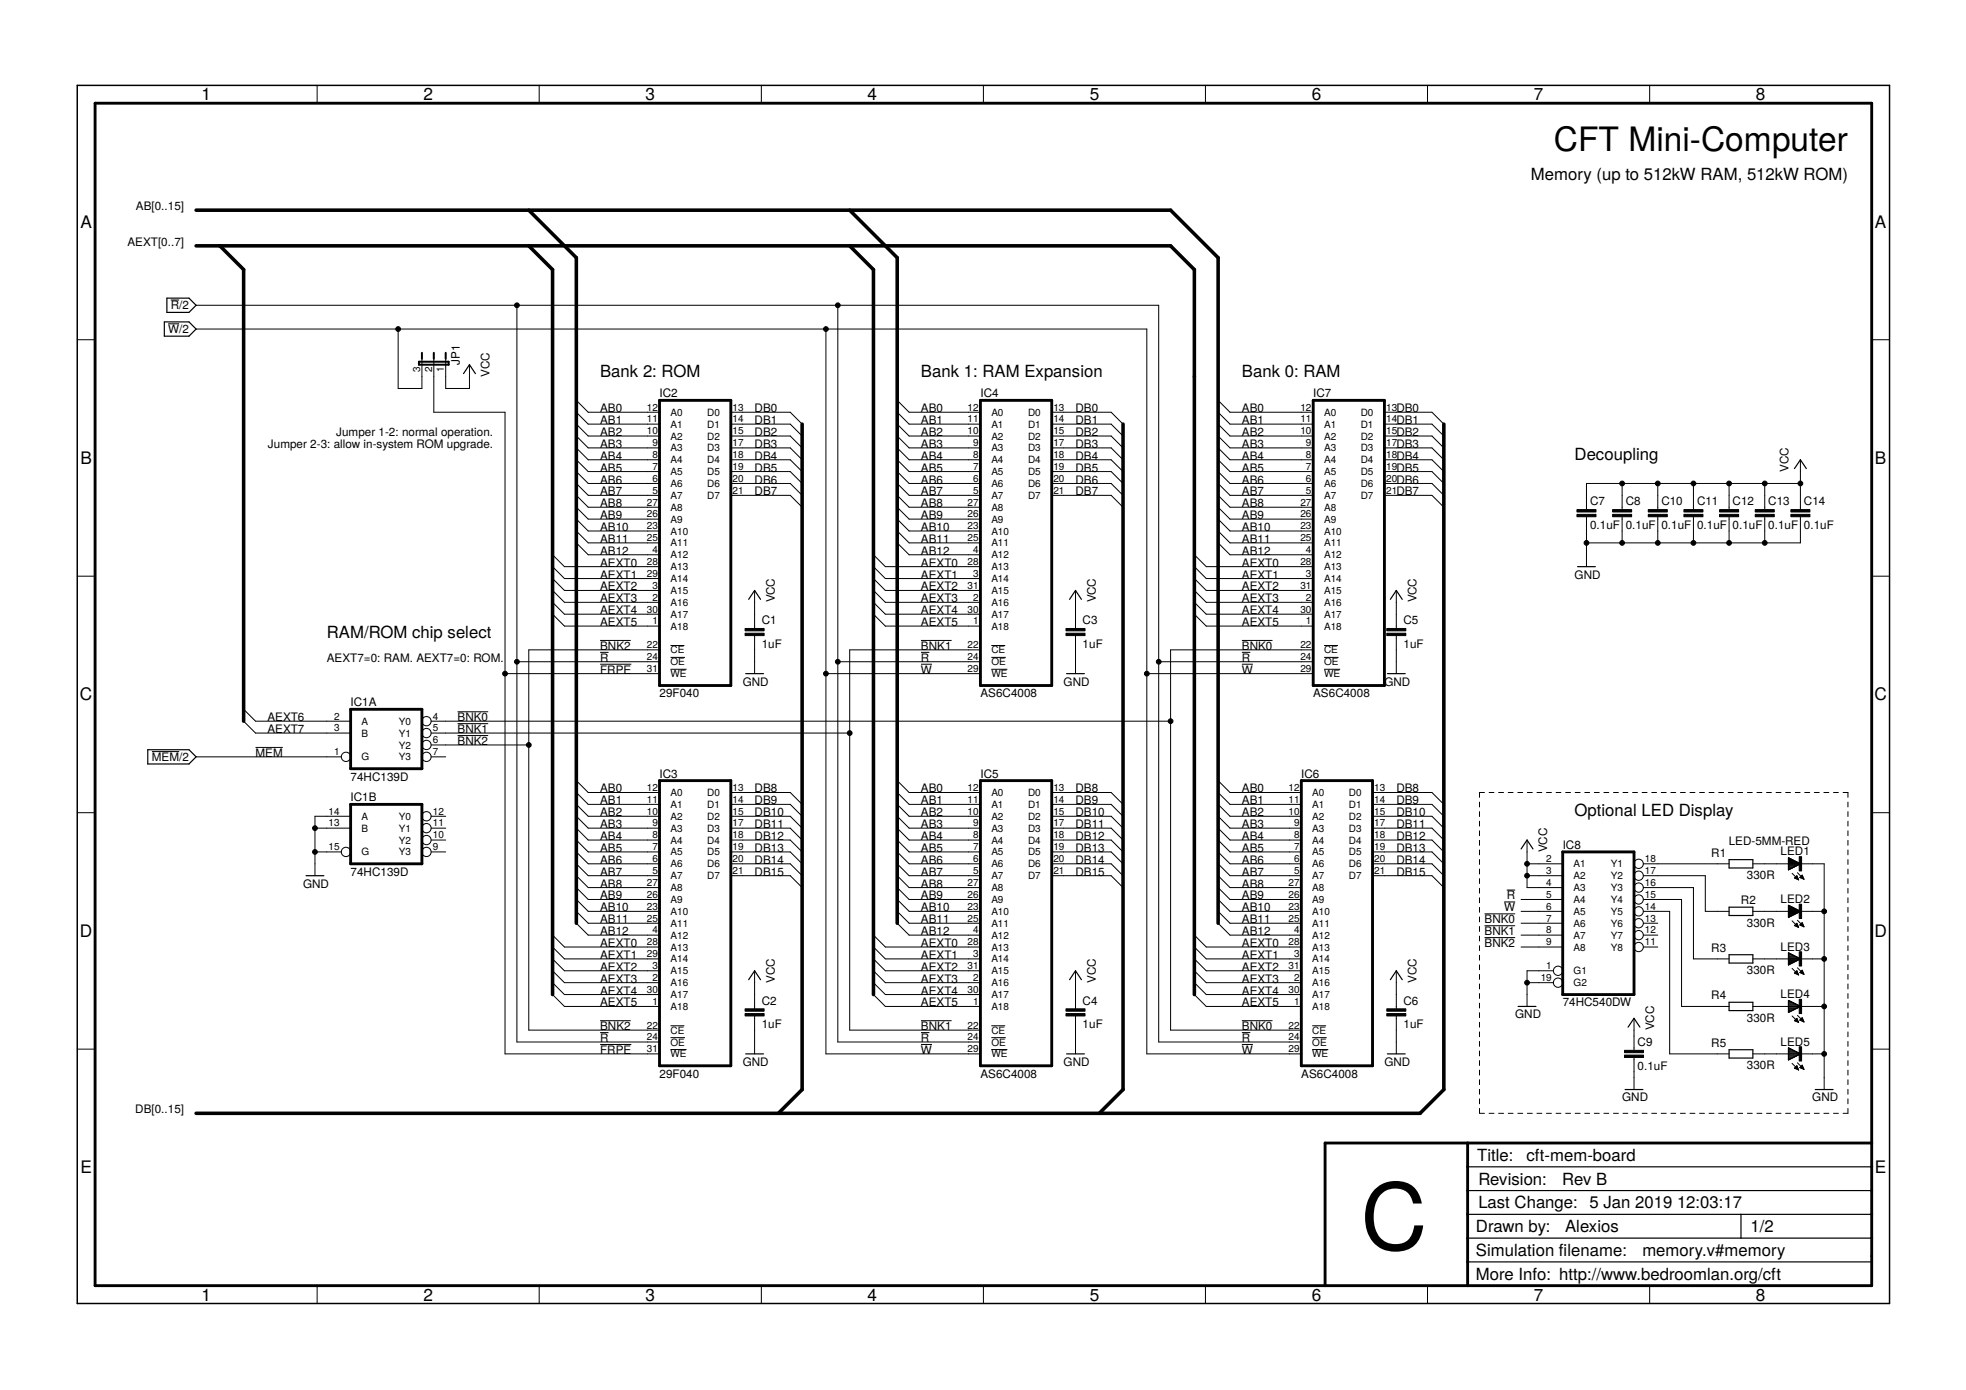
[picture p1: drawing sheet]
<svg xmlns="http://www.w3.org/2000/svg" width="420mm" height="297mm" viewBox="0 0 420 297" stroke-linecap="round" stroke-linejoin="round" font-family="sans-serif">
<defs><g id="words">
<text font-size="19.7" x="290.8" y="267.1">C</text>
<text font-size="7.2" x="332.1" y="32.2">CFT Mini-Computer</text>
<g font-size="3.7">
<text x="43" y="21.4">1</text>
<text x="90.5" y="21.4">2</text>
<text x="138" y="21.4">3</text>
<text x="185.4" y="21.4">4</text>
<text x="232.9" y="21.4">5</text>
<text x="280.3" y="21.4">6</text>
<text x="327.8" y="21.4">7</text>
<text x="375.3" y="21.4">8</text>
<text x="17.2" y="48.6">A</text>
<text x="400.7" y="48.6">A</text>
<text x="17.2" y="99.2">B</text>
<text x="400.7" y="99.2">B</text>
<text x="17.1" y="149.7">C</text>
<text x="400.6" y="149.7">C</text>
<text x="17.1" y="200.2">D</text>
<text x="400.6" y="200.2">D</text>
<text x="17.2" y="250.8">E</text>
<text x="400.7" y="250.8">E</text>
<text x="43" y="277.9">1</text>
<text x="90.5" y="277.9">2</text>
<text x="138" y="277.9">3</text>
<text x="185.4" y="277.9">4</text>
<text x="232.9" y="277.9">5</text>
<text x="280.3" y="277.9">6</text>
<text x="327.8" y="277.9">7</text>
<text x="375.3" y="277.9">8</text>
</g>
<g font-size="3.6">
<text x="327.2" y="38.6">Memory (up to 512kW RAM, 512kW ROM)</text>
<text x="128.3" y="80.5">Bank 2: ROM</text>
<text x="196.8" y="80.5">Bank 1: RAM Expansion</text>
<text x="265.4" y="80.5">Bank 0: RAM</text>
<text x="336.5" y="98.2">Decoupling</text>
<text x="69.8" y="136.3">RAM/ROM chip select</text>
<text x="336.5" y="174.4">Optional LED Display</text>
<text x="315.7" y="248.1">Title:</text>
<text x="326.2" y="248.2">cft-mem-board</text>
<text x="315.9" y="253.2">Revision:</text>
<text x="333.8" y="253.3">Rev B</text>
<text x="315.4" y="263.3">Drawn by:</text>
<text x="315.9" y="258.2">Last Change: 5 Jan 2019</text>
<text x="334.5" y="263.3">Alexios</text>
<text x="358.4" y="258.1">12:03:17</text>
<text x="374.1" y="263.2">1/2</text>
<text x="315.4" y="268.4">Simulation flename:</text>
<text x="333.2" y="268.4">i</text>
<text x="351" y="268.4">memory.v#memory</text>
<text x="315.4" y="273.5">More Info: http://www.bedroomlan.org/cft</text>
</g>
<g font-size="2.5">
<text x="29" y="44.9">AB[0..15]</text>
<text x="27.2" y="52.5">AEXT[0..7]</text>
<text x="35.9" y="71.2">W/2</text>
<text x="36.5" y="66.1">R/2</text>
<text x="98.3" y="77.9" transform="rotate(-90 98.3 77.9)">JP1</text>
<text x="104.6" y="80.5" transform="rotate(-90 104.6 80.5)">VCC</text>
<text x="128.3" y="88.1">AB0</text>
<text x="141" y="84.9">IC2</text>
<text x="161.3" y="88.1">DB0</text>
<text x="196.8" y="88.1">AB0</text>
<text x="209.5" y="84.9">IC4</text>
<text x="229.8" y="88.1">DB0</text>
<text x="265.4" y="88.1">AB0</text>
<text x="280.6" y="84.9">IC7</text>
<text x="298.4" y="88.1">DB0</text>
<text x="57.3" y="95.7">Jumper 2-3: allow in-system ROM upgrade.</text>
<text x="71.9" y="93.2">Jumper 1-2: normal operation.</text>
<text x="128.3" y="90.6">AB1</text>
<text x="128.3" y="93.2">AB2</text>
<text x="128.3" y="95.7">AB3</text>
<text x="161.3" y="90.6">DB1</text>
<text x="161.3" y="93.2">DB2</text>
<text x="161.3" y="95.7">DB3</text>
<text x="196.8" y="90.6">AB1</text>
<text x="196.8" y="93.2">AB2</text>
<text x="196.8" y="95.7">AB3</text>
<text x="229.8" y="90.6">DB1</text>
<text x="229.8" y="93.2">DB2</text>
<text x="229.8" y="95.7">DB3</text>
<text x="265.4" y="90.6">AB1</text>
<text x="265.4" y="93.2">AB2</text>
<text x="265.4" y="95.7">AB3</text>
<text x="298.4" y="90.6">DB1</text>
<text x="298.4" y="93.2">DB2</text>
<text x="298.4" y="95.7">DB3</text>
<text x="128.3" y="98.2">AB4</text>
<text x="128.3" y="100.8">AB5</text>
<text x="161.3" y="98.2">DB4</text>
<text x="161.3" y="100.8">DB5</text>
<text x="196.8" y="98.2">AB4</text>
<text x="196.8" y="100.8">AB5</text>
<text x="229.8" y="98.2">DB4</text>
<text x="229.8" y="100.8">DB5</text>
<text x="265.4" y="98.2">AB4</text>
<text x="265.4" y="100.8">AB5</text>
<text x="298.4" y="98.2">DB4</text>
<text x="298.4" y="100.8">DB5</text>
<text x="382.2" y="100.8" transform="rotate(-90 382.2 100.8)">VCC</text>
<text x="128.3" y="103.3">AB6</text>
<text x="128.3" y="105.9">AB7</text>
<text x="161.3" y="103.3">DB6</text>
<text x="161.3" y="105.9">DB7</text>
<text x="196.8" y="103.3">AB6</text>
<text x="196.8" y="105.9">AB7</text>
<text x="229.8" y="103.3">DB6</text>
<text x="229.8" y="105.9">DB7</text>
<text x="265.4" y="103.3">AB6</text>
<text x="265.4" y="105.9">AB7</text>
<text x="298.4" y="103.3">DB6</text>
<text x="298.4" y="105.9">DB7</text>
<text x="128.3" y="108.4">AB8</text>
<text x="128.3" y="110.9">AB9</text>
<text x="128.3" y="113.5">AB10</text>
<text x="196.8" y="108.4">AB8</text>
<text x="196.8" y="110.9">AB9</text>
<text x="196.8" y="113.5">AB10</text>
<text x="265.4" y="108.4">AB8</text>
<text x="265.4" y="110.9">AB9</text>
<text x="265.4" y="113.5">AB10</text>
<text x="339.8" y="113.1">0.1uF</text>
<text x="339.8" y="108">C7</text>
<text x="347.4" y="113.1">0.1uF</text>
<text x="347.4" y="108">C8</text>
<text x="355.1" y="113.1">0.1uF</text>
<text x="355.1" y="108">C10</text>
<text x="362.7" y="113.1">0.1uF</text>
<text x="362.7" y="108">C11</text>
<text x="370.3" y="113.1">0.1uF</text>
<text x="370.3" y="108">C12</text>
<text x="377.9" y="113.1">0.1uF</text>
<text x="377.9" y="108">C13</text>
<text x="385.5" y="113.1">0.1uF</text>
<text x="385.5" y="108">C14</text>
<text x="128.3" y="116">AB11</text>
<text x="128.3" y="118.6">AB12</text>
<text x="196.8" y="116">AB11</text>
<text x="196.8" y="118.6">AB12</text>
<text x="265.4" y="116">AB11</text>
<text x="265.4" y="118.6">AB12</text>
<text x="128.3" y="123.6">AEXT1</text>
<text x="128.3" y="121.1">AEXT0</text>
<text x="196.8" y="123.6">AEXT1</text>
<text x="196.8" y="121.1">AEXT0</text>
<text x="265.4" y="123.6">AEXT1</text>
<text x="265.4" y="121.1">AEXT0</text>
<text x="336.5" y="123.6">GND</text>
<text x="128.3" y="128.7">AEXT3</text>
<text x="128.3" y="131.3">AEXT4</text>
<text x="128.3" y="126.2">AEXT2</text>
<text x="165.6" y="128.7" transform="rotate(-90 165.6 128.7)">VCC</text>
<text x="196.8" y="128.7">AEXT3</text>
<text x="196.8" y="131.3">AEXT4</text>
<text x="196.8" y="126.2">AEXT2</text>
<text x="234.2" y="128.7" transform="rotate(-90 234.2 128.7)">VCC</text>
<text x="265.4" y="128.7">AEXT3</text>
<text x="265.4" y="131.3">AEXT4</text>
<text x="265.4" y="126.2">AEXT2</text>
<text x="302.7" y="128.7" transform="rotate(-90 302.7 128.7)">VCC</text>
<text x="128.3" y="133.8">AEXT5</text>
<text x="162.8" y="133.4">C1</text>
<text x="196.8" y="133.8">AEXT5</text>
<text x="231.4" y="133.4">C3</text>
<text x="265.4" y="133.8">AEXT5</text>
<text x="299.9" y="133.4">C5</text>
<text x="69.8" y="141.4">AEXT7=0: RAM. AEXT7=0: ROM.</text>
<text x="128.3" y="141.4">R</text>
<text x="128.3" y="144">FRPE</text>
<text x="128.3" y="138.9">BNK2</text>
<text x="162.8" y="138.5">1uF</text>
<text x="196.8" y="141.4">R</text>
<text x="196.8" y="144">W</text>
<text x="196.8" y="138.9">BNK1</text>
<text x="231.4" y="138.5">1uF</text>
<text x="265.4" y="141.4">R</text>
<text x="265.4" y="144">W</text>
<text x="265.4" y="138.9">BNK0</text>
<text x="299.9" y="138.5">1uF</text>
<text x="141" y="149">29F040</text>
<text x="158.7" y="146.5">GND</text>
<text x="209.5" y="149">AS6C4008</text>
<text x="227.3" y="146.5">GND</text>
<text x="280.6" y="149">AS6C4008</text>
<text x="295.9" y="146.5">GND</text>
<text x="57.1" y="154.1">AEXT6</text>
<text x="74.9" y="150.9">IC1A</text>
<text x="97.8" y="154.1">BNK0</text>
<text x="54.6" y="161.7">MEM</text>
<text x="57.1" y="156.7">AEXT7</text>
<text x="97.8" y="159.2">BNK2</text>
<text x="97.8" y="156.7">BNK1</text>
<text x="32.5" y="162.6">MEM/2</text>
<text x="74.9" y="166.8">74HC139D</text>
<text x="141" y="166.2">IC3</text>
<text x="209.5" y="166.2">IC5</text>
<text x="278.1" y="166.2">IC6</text>
<text x="74.9" y="171.3">IC1B</text>
<text x="128.3" y="169.4">AB0</text>
<text x="128.3" y="171.9">AB1</text>
<text x="161.3" y="169.4">DB8</text>
<text x="161.3" y="171.9">DB9</text>
<text x="196.8" y="169.4">AB0</text>
<text x="196.8" y="171.9">AB1</text>
<text x="229.8" y="169.4">DB8</text>
<text x="229.8" y="171.9">DB9</text>
<text x="265.4" y="169.4">AB0</text>
<text x="265.4" y="171.9">AB1</text>
<text x="298.4" y="169.4">DB8</text>
<text x="298.4" y="171.9">DB9</text>
<text x="128.3" y="174.4">AB2</text>
<text x="128.3" y="177">AB3</text>
<text x="128.3" y="179.5">AB4</text>
<text x="161.3" y="174.4">DB10</text>
<text x="161.3" y="177">DB11</text>
<text x="161.3" y="179.5">DB12</text>
<text x="196.8" y="174.4">AB2</text>
<text x="196.8" y="177">AB3</text>
<text x="196.8" y="179.5">AB4</text>
<text x="229.8" y="174.4">DB10</text>
<text x="229.8" y="177">DB11</text>
<text x="229.8" y="179.5">DB12</text>
<text x="265.4" y="174.4">AB2</text>
<text x="265.4" y="177">AB3</text>
<text x="265.4" y="179.5">AB4</text>
<text x="298.4" y="174.4">DB10</text>
<text x="298.4" y="177">DB11</text>
<text x="298.4" y="179.5">DB12</text>
<text x="128.3" y="182.1">AB5</text>
<text x="128.3" y="184.6">AB6</text>
<text x="161.3" y="182.1">DB13</text>
<text x="161.3" y="184.6">DB14</text>
<text x="196.8" y="182.1">AB5</text>
<text x="196.8" y="184.6">AB6</text>
<text x="229.8" y="182.1">DB13</text>
<text x="229.8" y="184.6">DB14</text>
<text x="265.4" y="182.1">AB5</text>
<text x="265.4" y="184.6">AB6</text>
<text x="298.4" y="182.1">DB13</text>
<text x="298.4" y="184.6">DB14</text>
<text x="330.7" y="182.1" transform="rotate(-90 330.7 182.1)">VCC</text>
<text x="334" y="181.4">IC8</text>
<text x="365.7" y="183.1">R1</text>
<text x="369.5" y="180.7">LED-5MM-RED</text>
<text x="380.5" y="182.8">LED1</text>
<text x="64.8" y="189.7">GND</text>
<text x="74.9" y="187.1">74HC139D</text>
<text x="128.3" y="187.1">AB7</text>
<text x="128.3" y="189.7">AB8</text>
<text x="161.3" y="187.1">DB15</text>
<text x="196.8" y="187.1">AB7</text>
<text x="196.8" y="189.7">AB8</text>
<text x="229.8" y="187.1">DB15</text>
<text x="265.4" y="187.1">AB7</text>
<text x="265.4" y="189.7">AB8</text>
<text x="298.4" y="187.1">DB15</text>
<text x="373.3" y="187.9">330R</text>
<text x="128.3" y="192.2">AB9</text>
<text x="128.3" y="194.7">AB10</text>
<text x="128.3" y="197.3">AB11</text>
<text x="196.8" y="192.2">AB9</text>
<text x="196.8" y="194.7">AB10</text>
<text x="196.8" y="197.3">AB11</text>
<text x="265.4" y="192.2">AB9</text>
<text x="265.4" y="194.7">AB10</text>
<text x="265.4" y="197.3">AB11</text>
<text x="317.3" y="197.3">BNK0</text>
<text x="321.5" y="194.7">W</text>
<text x="322" y="192.2">R</text>
<text x="372.1" y="193.2">R2</text>
<text x="380.5" y="193">LED2</text>
<text x="128.3" y="202.4">AEXT0</text>
<text x="128.3" y="199.8">AB12</text>
<text x="196.8" y="202.4">AEXT0</text>
<text x="196.8" y="199.8">AB12</text>
<text x="265.4" y="202.4">AEXT0</text>
<text x="265.4" y="199.8">AB12</text>
<text x="317.3" y="202.4">BNK2</text>
<text x="317.3" y="199.8">BNK1</text>
<text x="365.7" y="203.4">R3</text>
<text x="373.3" y="198">330R</text>
<text x="380.5" y="203.1">LED3</text>
<text x="128.3" y="210">AEXT3</text>
<text x="128.3" y="207.4">AEXT2</text>
<text x="128.3" y="204.9">AEXT1</text>
<text x="165.6" y="210" transform="rotate(-90 165.6 210)">VCC</text>
<text x="196.8" y="210">AEXT3</text>
<text x="196.8" y="207.4">AEXT2</text>
<text x="196.8" y="204.9">AEXT1</text>
<text x="234.2" y="210" transform="rotate(-90 234.2 210)">VCC</text>
<text x="265.4" y="210">AEXT3</text>
<text x="265.4" y="207.4">AEXT2</text>
<text x="265.4" y="204.9">AEXT1</text>
<text x="302.7" y="210" transform="rotate(-90 302.7 210)">VCC</text>
<text x="373.3" y="208.2">330R</text>
<text x="128.3" y="212.5">AEXT4</text>
<text x="128.3" y="215.1">AEXT5</text>
<text x="162.8" y="214.7">C2</text>
<text x="196.8" y="212.5">AEXT4</text>
<text x="196.8" y="215.1">AEXT5</text>
<text x="231.4" y="214.7">C4</text>
<text x="265.4" y="212.5">AEXT4</text>
<text x="265.4" y="215.1">AEXT5</text>
<text x="299.9" y="214.7">C6</text>
<text x="334" y="215.1">74HC540DW</text>
<text x="365.7" y="213.6">R4</text>
<text x="380.5" y="213.3">LED4</text>
<text x="128.3" y="220.1">BNK2</text>
<text x="162.8" y="219.8">1uF</text>
<text x="196.8" y="220.1">BNK1</text>
<text x="231.4" y="219.8">1uF</text>
<text x="265.4" y="220.1">BNK0</text>
<text x="299.9" y="219.8">1uF</text>
<text x="323.8" y="217.6">GND</text>
<text x="353.5" y="220.1" transform="rotate(-90 353.5 220.1)">VCC</text>
<text x="373.3" y="218.4">330R</text>
<text x="128.3" y="222.7">R</text>
<text x="128.3" y="225.2">FRPE</text>
<text x="158.7" y="227.8">GND</text>
<text x="196.8" y="222.7">R</text>
<text x="196.8" y="225.2">W</text>
<text x="227.3" y="227.8">GND</text>
<text x="265.4" y="222.7">R</text>
<text x="265.4" y="225.2">W</text>
<text x="295.9" y="227.8">GND</text>
<text x="350" y="223.6">C9</text>
<text x="365.7" y="223.7">R5</text>
<text x="380.5" y="223.4">LED5</text>
<text x="141" y="230.3">29F040</text>
<text x="209.5" y="230.3">AS6C4008</text>
<text x="278.1" y="230.3">AS6C4008</text>
<text x="350" y="228.7">0.1uF</text>
<text x="373.3" y="228.5">330R</text>
<text x="28.9" y="237.9">DB[0..15]</text>
<text x="346.7" y="235.4">GND</text>
<text x="387.3" y="235.4">GND</text>
</g>
<g font-size="2.1">
<text x="89.8" y="79.5" transform="rotate(-90 89.8 79.5)">3</text>
<text x="92.3" y="79.5" transform="rotate(-90 92.3 79.5)">2</text>
<text x="94.9" y="79.5" transform="rotate(-90 94.9 79.5)">1</text>
<text x="138.2" y="87.7">12</text>
<text x="143.3" y="88.8">A0</text>
<text x="151.1" y="88.8">D0</text>
<text x="156.5" y="87.7">13</text>
<text x="206.8" y="87.7">12</text>
<text x="211.9" y="88.8">A0</text>
<text x="219.7" y="88.8">D0</text>
<text x="225.1" y="87.7">13</text>
<text x="277.9" y="87.7">12</text>
<text x="283" y="88.8">A0</text>
<text x="290.8" y="88.8">D0</text>
<text x="296.2" y="87.7">13</text>
<text x="138.2" y="92.8">10</text>
<text x="138.2" y="90.3">11</text>
<text x="139.4" y="95.4">9</text>
<text x="143.3" y="93.9">A2</text>
<text x="143.3" y="91.4">A1</text>
<text x="151.1" y="91.4">D1</text>
<text x="151.1" y="93.9">D2</text>
<text x="156.5" y="90.3">14</text>
<text x="156.5" y="92.8">15</text>
<text x="156.5" y="95.4">17</text>
<text x="206.8" y="92.8">10</text>
<text x="206.8" y="90.3">11</text>
<text x="208" y="95.4">9</text>
<text x="211.9" y="93.9">A2</text>
<text x="211.9" y="91.4">A1</text>
<text x="219.7" y="91.4">D1</text>
<text x="219.7" y="93.9">D2</text>
<text x="225.1" y="90.3">14</text>
<text x="225.1" y="92.8">15</text>
<text x="225.1" y="95.4">17</text>
<text x="277.9" y="92.8">10</text>
<text x="277.9" y="90.3">11</text>
<text x="279.1" y="95.4">9</text>
<text x="283" y="93.9">A2</text>
<text x="283" y="91.4">A1</text>
<text x="290.8" y="91.4">D1</text>
<text x="290.8" y="93.9">D2</text>
<text x="296.2" y="90.3">14</text>
<text x="296.2" y="92.8">15</text>
<text x="296.2" y="95.4">17</text>
<text x="139.4" y="100.4">7</text>
<text x="139.4" y="97.9">8</text>
<text x="143.3" y="101.5">A5</text>
<text x="143.3" y="99">A4</text>
<text x="143.3" y="96.5">A3</text>
<text x="151.1" y="96.5">D3</text>
<text x="151.1" y="99">D4</text>
<text x="151.1" y="101.5">D5</text>
<text x="156.5" y="97.9">18</text>
<text x="156.5" y="100.4">19</text>
<text x="208" y="100.4">7</text>
<text x="208" y="97.9">8</text>
<text x="211.9" y="101.5">A5</text>
<text x="211.9" y="99">A4</text>
<text x="211.9" y="96.5">A3</text>
<text x="219.7" y="96.5">D3</text>
<text x="219.7" y="99">D4</text>
<text x="219.7" y="101.5">D5</text>
<text x="225.1" y="97.9">18</text>
<text x="225.1" y="100.4">19</text>
<text x="279.1" y="100.4">7</text>
<text x="279.1" y="97.9">8</text>
<text x="283" y="101.5">A5</text>
<text x="283" y="99">A4</text>
<text x="283" y="96.5">A3</text>
<text x="290.8" y="96.5">D3</text>
<text x="290.8" y="99">D4</text>
<text x="290.8" y="101.5">D5</text>
<text x="296.2" y="97.9">18</text>
<text x="296.2" y="100.4">19</text>
<text x="139.4" y="105.5">5</text>
<text x="139.4" y="103">6</text>
<text x="143.3" y="106.6">A7</text>
<text x="143.3" y="104.1">A6</text>
<text x="151.1" y="104.1">D6</text>
<text x="151.1" y="106.6">D7</text>
<text x="156.5" y="103">20</text>
<text x="156.5" y="105.5">21</text>
<text x="208" y="105.5">5</text>
<text x="208" y="103">6</text>
<text x="211.9" y="106.6">A7</text>
<text x="211.9" y="104.1">A6</text>
<text x="219.7" y="104.1">D6</text>
<text x="219.7" y="106.6">D7</text>
<text x="225.1" y="103">20</text>
<text x="225.1" y="105.5">21</text>
<text x="279.1" y="105.5">5</text>
<text x="279.1" y="103">6</text>
<text x="283" y="106.6">A7</text>
<text x="283" y="104.1">A6</text>
<text x="290.8" y="104.1">D6</text>
<text x="290.8" y="106.6">D7</text>
<text x="296.2" y="103">20</text>
<text x="296.2" y="105.5">21</text>
<text x="138.2" y="113.1">23</text>
<text x="138.2" y="110.6">26</text>
<text x="138.2" y="108">27</text>
<text x="143.3" y="111.7">A9</text>
<text x="143.3" y="109.2">A8</text>
<text x="206.8" y="113.1">23</text>
<text x="206.8" y="110.6">26</text>
<text x="206.8" y="108">27</text>
<text x="211.9" y="111.7">A9</text>
<text x="211.9" y="109.2">A8</text>
<text x="277.9" y="113.1">23</text>
<text x="277.9" y="110.6">26</text>
<text x="277.9" y="108">27</text>
<text x="283" y="111.7">A9</text>
<text x="283" y="109.2">A8</text>
<text x="138.2" y="115.7">25</text>
<text x="139.4" y="118.2">4</text>
<text x="143.3" y="119.3">A12</text>
<text x="143.3" y="114.2">A10</text>
<text x="143.3" y="116.8">A11</text>
<text x="206.8" y="115.7">25</text>
<text x="208" y="118.2">4</text>
<text x="211.9" y="119.3">A12</text>
<text x="211.9" y="114.2">A10</text>
<text x="211.9" y="116.8">A11</text>
<text x="277.9" y="115.7">25</text>
<text x="279.1" y="118.2">4</text>
<text x="283" y="119.3">A12</text>
<text x="283" y="114.2">A10</text>
<text x="283" y="116.8">A11</text>
<text x="138.2" y="120.7">28</text>
<text x="138.2" y="123.3">29</text>
<text x="139.4" y="125.8">3</text>
<text x="143.3" y="121.9">A13</text>
<text x="143.3" y="124.4">A14</text>
<text x="206.8" y="120.7">28</text>
<text x="206.8" y="125.8">31</text>
<text x="208" y="123.3">3</text>
<text x="211.9" y="121.9">A13</text>
<text x="211.9" y="124.4">A14</text>
<text x="277.9" y="120.7">28</text>
<text x="277.9" y="125.8">31</text>
<text x="279.1" y="123.3">3</text>
<text x="283" y="121.9">A13</text>
<text x="283" y="124.4">A14</text>
<text x="138.2" y="130.9">30</text>
<text x="139.4" y="128.4">2</text>
<text x="143.3" y="126.9">A15</text>
<text x="143.3" y="129.5">A16</text>
<text x="206.8" y="130.9">30</text>
<text x="208" y="128.4">2</text>
<text x="211.9" y="126.9">A15</text>
<text x="211.9" y="129.5">A16</text>
<text x="277.9" y="130.9">30</text>
<text x="279.1" y="128.4">2</text>
<text x="283" y="126.9">A15</text>
<text x="283" y="129.5">A16</text>
<text x="139.4" y="133.4">1</text>
<text x="143.3" y="132">A17</text>
<text x="143.3" y="134.6">A18</text>
<text x="208" y="133.4">1</text>
<text x="211.9" y="132">A17</text>
<text x="211.9" y="134.6">A18</text>
<text x="279.1" y="133.4">1</text>
<text x="283" y="132">A17</text>
<text x="283" y="134.6">A18</text>
<text x="138.2" y="143.6">31</text>
<text x="138.2" y="138.5">22</text>
<text x="138.2" y="141.1">24</text>
<text x="143.3" y="139.6">CE</text>
<text x="143.3" y="142.2">OE</text>
<text x="206.8" y="143.6">29</text>
<text x="206.8" y="138.5">22</text>
<text x="206.8" y="141.1">24</text>
<text x="211.9" y="139.6">CE</text>
<text x="211.9" y="142.2">OE</text>
<text x="277.9" y="143.6">29</text>
<text x="277.9" y="138.5">22</text>
<text x="277.9" y="141.1">24</text>
<text x="283" y="139.6">CE</text>
<text x="283" y="142.2">OE</text>
<text x="143.3" y="144.7">WE</text>
<text x="211.9" y="144.7">WE</text>
<text x="283" y="144.7">WE</text>
<text x="71.4" y="153.8">2</text>
<text x="77.3" y="154.9">A</text>
<text x="85.2" y="154.9">Y0</text>
<text x="92.5" y="153.8">4</text>
<text x="71.4" y="161.4">1</text>
<text x="71.4" y="156.3">3</text>
<text x="77.3" y="157.4">B</text>
<text x="85.2" y="157.4">Y1</text>
<text x="85.2" y="160">Y2</text>
<text x="92.5" y="156.3">5</text>
<text x="92.5" y="158.8">6</text>
<text x="92.5" y="161.4">7</text>
<text x="77.3" y="162.5">G</text>
<text x="85.2" y="162.5">Y3</text>
<text x="138.2" y="171.5">11</text>
<text x="138.2" y="169">12</text>
<text x="143.3" y="172.7">A1</text>
<text x="143.3" y="170.1">A0</text>
<text x="151.1" y="170.1">D0</text>
<text x="151.1" y="172.7">D1</text>
<text x="156.5" y="169">13</text>
<text x="156.5" y="171.5">14</text>
<text x="206.8" y="171.5">11</text>
<text x="206.8" y="169">12</text>
<text x="211.9" y="172.7">A1</text>
<text x="211.9" y="170.1">A0</text>
<text x="219.7" y="170.1">D0</text>
<text x="219.7" y="172.7">D1</text>
<text x="225.1" y="169">13</text>
<text x="225.1" y="171.5">14</text>
<text x="275.4" y="171.5">11</text>
<text x="275.4" y="169">12</text>
<text x="280.4" y="172.7">A1</text>
<text x="280.4" y="170.1">A0</text>
<text x="288.3" y="170.1">D0</text>
<text x="288.3" y="172.7">D1</text>
<text x="293.7" y="169">13</text>
<text x="293.7" y="171.5">14</text>
<text x="70.2" y="174.1">14</text>
<text x="70.2" y="176.6">13</text>
<text x="77.3" y="175.2">A</text>
<text x="77.3" y="177.7">B</text>
<text x="85.2" y="175.2">Y0</text>
<text x="85.2" y="177.7">Y1</text>
<text x="92.5" y="174.1">12</text>
<text x="92.5" y="176.6">11</text>
<text x="92.5" y="179.2">10</text>
<text x="138.2" y="174.1">10</text>
<text x="139.4" y="179.2">8</text>
<text x="139.4" y="176.6">9</text>
<text x="143.3" y="177.7">A3</text>
<text x="143.3" y="175.2">A2</text>
<text x="151.1" y="175.2">D2</text>
<text x="151.1" y="177.7">D3</text>
<text x="156.5" y="174.1">15</text>
<text x="156.5" y="176.6">17</text>
<text x="156.5" y="179.2">18</text>
<text x="206.8" y="174.1">10</text>
<text x="208" y="179.2">8</text>
<text x="208" y="176.6">9</text>
<text x="211.9" y="177.7">A3</text>
<text x="211.9" y="175.2">A2</text>
<text x="219.7" y="175.2">D2</text>
<text x="219.7" y="177.7">D3</text>
<text x="225.1" y="174.1">15</text>
<text x="225.1" y="176.6">17</text>
<text x="225.1" y="179.2">18</text>
<text x="275.4" y="174.1">10</text>
<text x="276.6" y="179.2">8</text>
<text x="276.6" y="176.6">9</text>
<text x="280.4" y="177.7">A3</text>
<text x="280.4" y="175.2">A2</text>
<text x="288.3" y="175.2">D2</text>
<text x="288.3" y="177.7">D3</text>
<text x="293.7" y="174.1">15</text>
<text x="293.7" y="176.6">17</text>
<text x="293.7" y="179.2">18</text>
<text x="70.2" y="181.7">15</text>
<text x="77.3" y="182.8">G</text>
<text x="85.2" y="180.3">Y2</text>
<text x="85.2" y="182.8">Y3</text>
<text x="92.5" y="181.7">9</text>
<text x="139.4" y="184.2">6</text>
<text x="139.4" y="181.7">7</text>
<text x="143.3" y="185.4">A6</text>
<text x="143.3" y="182.8">A5</text>
<text x="143.3" y="180.3">A4</text>
<text x="151.1" y="180.3">D4</text>
<text x="151.1" y="182.8">D5</text>
<text x="151.1" y="185.4">D6</text>
<text x="156.5" y="181.7">19</text>
<text x="156.5" y="184.2">20</text>
<text x="208" y="184.2">6</text>
<text x="208" y="181.7">7</text>
<text x="211.9" y="185.4">A6</text>
<text x="211.9" y="182.8">A5</text>
<text x="211.9" y="180.3">A4</text>
<text x="219.7" y="180.3">D4</text>
<text x="219.7" y="182.8">D5</text>
<text x="219.7" y="185.4">D6</text>
<text x="225.1" y="181.7">19</text>
<text x="225.1" y="184.2">20</text>
<text x="276.6" y="184.2">6</text>
<text x="276.6" y="181.7">7</text>
<text x="280.4" y="185.4">A6</text>
<text x="280.4" y="182.8">A5</text>
<text x="280.4" y="180.3">A4</text>
<text x="288.3" y="180.3">D4</text>
<text x="288.3" y="182.8">D5</text>
<text x="288.3" y="185.4">D6</text>
<text x="293.7" y="181.7">19</text>
<text x="293.7" y="184.2">20</text>
<text x="330.5" y="184.2">2</text>
<text x="336.3" y="185.4">A1</text>
<text x="344.3" y="185.4">Y1</text>
<text x="351.5" y="184.2">18</text>
<text x="138.2" y="191.9">26</text>
<text x="138.2" y="189.3">27</text>
<text x="139.4" y="186.8">5</text>
<text x="143.3" y="187.9">A7</text>
<text x="143.3" y="190.4">A8</text>
<text x="151.1" y="187.9">D7</text>
<text x="156.5" y="186.8">21</text>
<text x="206.8" y="191.9">26</text>
<text x="206.8" y="189.3">27</text>
<text x="208" y="186.8">5</text>
<text x="211.9" y="187.9">A7</text>
<text x="211.9" y="190.4">A8</text>
<text x="219.7" y="187.9">D7</text>
<text x="225.1" y="186.8">21</text>
<text x="275.4" y="191.9">26</text>
<text x="275.4" y="189.3">27</text>
<text x="276.6" y="186.8">5</text>
<text x="280.4" y="187.9">A7</text>
<text x="280.4" y="190.4">A8</text>
<text x="288.3" y="187.9">D7</text>
<text x="293.7" y="186.8">21</text>
<text x="330.5" y="186.8">3</text>
<text x="330.5" y="189.3">4</text>
<text x="330.5" y="191.9">5</text>
<text x="336.3" y="187.9">A2</text>
<text x="336.3" y="190.4">A3</text>
<text x="344.3" y="190.4">Y3</text>
<text x="344.3" y="187.9">Y2</text>
<text x="351.5" y="191.9">15</text>
<text x="351.5" y="189.3">16</text>
<text x="351.5" y="186.8">17</text>
<text x="138.2" y="194.4">23</text>
<text x="138.2" y="196.9">25</text>
<text x="143.3" y="195.5">A10</text>
<text x="143.3" y="193">A9</text>
<text x="206.8" y="194.4">23</text>
<text x="206.8" y="196.9">25</text>
<text x="211.9" y="195.5">A10</text>
<text x="211.9" y="193">A9</text>
<text x="275.4" y="194.4">23</text>
<text x="275.4" y="196.9">25</text>
<text x="280.4" y="195.5">A10</text>
<text x="280.4" y="193">A9</text>
<text x="330.5" y="194.4">6</text>
<text x="330.5" y="196.9">7</text>
<text x="336.3" y="193">A4</text>
<text x="336.3" y="195.5">A5</text>
<text x="344.3" y="195.5">Y5</text>
<text x="344.3" y="193">Y4</text>
<text x="351.5" y="196.9">13</text>
<text x="351.5" y="194.4">14</text>
<text x="138.2" y="202">28</text>
<text x="139.4" y="199.5">4</text>
<text x="143.3" y="200.6">A12</text>
<text x="143.3" y="198">A11</text>
<text x="143.3" y="203.1">A13</text>
<text x="206.8" y="202">28</text>
<text x="208" y="199.5">4</text>
<text x="211.9" y="200.6">A12</text>
<text x="211.9" y="198">A11</text>
<text x="211.9" y="203.1">A13</text>
<text x="275.4" y="202">28</text>
<text x="276.6" y="199.5">4</text>
<text x="280.4" y="200.6">A12</text>
<text x="280.4" y="198">A11</text>
<text x="280.4" y="203.1">A13</text>
<text x="330.5" y="199.5">8</text>
<text x="330.5" y="202">9</text>
<text x="336.3" y="198">A6</text>
<text x="336.3" y="200.6">A7</text>
<text x="336.3" y="203.1">A8</text>
<text x="344.3" y="203.1">Y8</text>
<text x="344.3" y="200.6">Y7</text>
<text x="344.3" y="198">Y6</text>
<text x="351.5" y="202">11</text>
<text x="351.5" y="199.5">12</text>
<text x="138.2" y="204.6">29</text>
<text x="139.4" y="207.1">3</text>
<text x="139.4" y="209.6">2</text>
<text x="143.3" y="205.7">A14</text>
<text x="143.3" y="208.2">A15</text>
<text x="206.8" y="207.1">31</text>
<text x="208" y="204.6">3</text>
<text x="208" y="209.6">2</text>
<text x="211.9" y="205.7">A14</text>
<text x="211.9" y="208.2">A15</text>
<text x="275.4" y="207.1">31</text>
<text x="276.6" y="204.6">3</text>
<text x="276.6" y="209.6">2</text>
<text x="280.4" y="205.7">A14</text>
<text x="280.4" y="208.2">A15</text>
<text x="329.3" y="209.6">19</text>
<text x="330.5" y="207.1">1</text>
<text x="336.3" y="208.2">G1</text>
<text x="138.2" y="212.2">30</text>
<text x="139.4" y="214.7">1</text>
<text x="143.3" y="210.7">A16</text>
<text x="143.3" y="213.3">A17</text>
<text x="143.3" y="215.8">A18</text>
<text x="206.8" y="212.2">30</text>
<text x="208" y="214.7">1</text>
<text x="211.9" y="210.7">A16</text>
<text x="211.9" y="213.3">A17</text>
<text x="211.9" y="215.8">A18</text>
<text x="275.4" y="212.2">30</text>
<text x="276.6" y="214.7">1</text>
<text x="280.4" y="210.7">A16</text>
<text x="280.4" y="213.3">A17</text>
<text x="280.4" y="215.8">A18</text>
<text x="336.3" y="210.7">G2</text>
<text x="138.2" y="219.8">22</text>
<text x="143.3" y="220.9">CE</text>
<text x="206.8" y="219.8">22</text>
<text x="211.9" y="220.9">CE</text>
<text x="275.4" y="219.8">22</text>
<text x="280.4" y="220.9">CE</text>
<text x="138.2" y="224.9">31</text>
<text x="138.2" y="222.3">24</text>
<text x="143.3" y="226">WE</text>
<text x="143.3" y="223.4">OE</text>
<text x="206.8" y="224.9">29</text>
<text x="206.8" y="222.3">24</text>
<text x="211.9" y="226">WE</text>
<text x="211.9" y="223.4">OE</text>
<text x="275.4" y="224.9">29</text>
<text x="275.4" y="222.3">24</text>
<text x="280.4" y="226">WE</text>
<text x="280.4" y="223.4">OE</text>
</g>
</g></defs>
<g fill="none" stroke="#000" stroke-width=".21">
<path d="M67.8 18.2v3.9M115.2 18.2v3.9M162.7 18.2v3.9M210.2 18.2v3.9M257.6 18.2v3.9M305.1 18.2v3.9M352.6 18.2v3.9M20.3 22.1h379.7v252.6h-379.7zM16.5 72.6h3.8M35.9 69.2h2.4M36.5 64.1h1.8M41.9 70.3h203.2v154.9h33"/>
<path d="M41.9 65.2h205.7v157.5h30.5M85.1 70.3v12.7h5.1v-6.3M92.7 76.7v11.4h15.2v137.1h33M95.2 76.7v6.3h5.1v-5.1M110.5 65.2v157.5h30.4M176.5 70.3v154.9h33M179 65.2v157.5h30.5M400 72.6h3.8M123.2 98.3l2.5 2.5h15.2M123.2 95.7l2.5 2.6h15.2M123.2 93.2l2.5 2.5h15.2M123.2 90.6l2.5 2.6h15.2"/>
<path d="M123.2 88.1l2.5 2.5h15.2M123.2 85.6l2.5 2.5h15.2M156.2 98.3h12.7l2.5 2.5M156.2 95.7h12.7l2.5 2.6M156.2 93.2h12.7l2.5 2.5M156.2 90.6h12.7l2.5 2.6M156.2 88.1h12.7l2.5 2.5M191.7 98.3l2.6 2.5h15.2M191.7 95.7l2.6 2.6h15.2M191.7 93.2l2.6 2.5h15.2M191.7 90.6l2.6 2.6h15.2M191.7 88.1l2.6 2.5h15.2"/>
<path d="M191.7 85.6l2.6 2.5h15.2M224.8 98.3h12.7l2.5 2.5M224.8 95.7h12.7l2.5 2.6M224.8 93.2h12.7l2.5 2.5M224.8 90.6h12.7l2.5 2.6M224.8 88.1h12.7l2.5 2.5M260.3 98.3l2.6 2.5h17.7M260.3 95.7l2.6 2.6h17.7M260.3 93.2l2.6 2.5h17.7M260.3 90.6l2.6 2.6h17.7M260.3 88.1l2.6 2.5h17.7M260.3 85.6l2.6 2.5h17.7"/>
<path d="M295.9 98.3h10.1l2.6 2.5M295.9 95.7h10.1l2.6 2.6M295.9 93.2h10.1l2.6 2.5M295.9 90.6h10.1l2.6 2.6M295.9 88.1h10.1l2.6 2.5M384.8 98.3v10.6M118.1 118.6l2.5 2.5h20.3M123.2 116l2.5 2.6h15.2M123.2 103.3l2.5 2.6h15.2M123.2 100.8l2.5 2.5h15.2M123.2 110.9l2.5 2.6h15.2M123.2 113.5l2.5 2.5h15.2"/>
<path d="M123.2 108.4l2.5 2.5h15.2M123.2 105.9l2.5 2.5h15.2M156.2 105.9h12.7l2.5 2.5M156.2 103.3h12.7l2.5 2.6M156.2 100.8h12.7l2.5 2.5M186.7 118.6l2.5 2.5h20.3M191.7 116l2.6 2.6h15.2M191.7 103.3l2.6 2.6h15.2M191.7 100.8l2.6 2.5h15.2M191.7 110.9l2.6 2.6h15.2M191.7 113.5l2.6 2.5h15.2M191.7 108.4l2.6 2.5h15.2"/>
<path d="M191.7 105.9l2.6 2.5h15.2M224.8 105.9h12.7l2.5 2.5M224.8 103.3h12.7l2.5 2.6M224.8 100.8h12.7l2.5 2.5M255.2 118.6l2.6 2.5h22.8M260.3 116l2.6 2.6h17.7M260.3 103.3l2.6 2.6h17.7M260.3 100.8l2.6 2.5h17.7M260.3 110.9l2.6 2.6h17.7M260.3 113.5l2.6 2.5h17.7M260.3 108.4l2.6 2.5h17.7M260.3 105.9l2.6 2.5h17.7"/>
<path d="M295.9 105.9h10.1l2.6 2.5M295.9 103.3h10.1l2.6 2.6M295.9 100.8h10.1l2.6 2.5M339 110.4v10.7M346.7 103.3v5.6M346.7 110.4v5.6M354.3 103.3v5.6M354.3 110.4v5.6M361.9 103.3v5.6M361.9 110.4v5.6M369.5 103.3v5.6M369.5 110.4v5.6"/>
<path d="M377.1 103.3v5.6M377.1 110.4v5.6M384.8 110.4v5.6h-45.8M384.8 103.3h-45.8v5.6M16.5 123.1h3.8M118.1 121.1l2.5 2.5h20.3M118.1 123.6l2.5 2.6h20.3M118.1 126.2l2.5 2.5h20.3M118.1 128.7l2.5 2.6h20.3M118.1 131.3l2.5 2.5h20.3M128.2 139.4h1.8M128.2 136.9h6.6"/>
<path d="M140.9 138.9h-27.9v81.2h27.9M143.3 137.9h3M161.3 126.2v8.1M161.3 135.8v8.2M186.7 121.1l2.5 2.5h20.3M186.7 123.6l2.5 2.6h20.3M186.7 126.2l2.5 2.5h20.3M186.7 128.7l2.5 2.6h20.3M186.7 131.3l2.5 2.5h20.3M196.8 139.4h1.8M196.8 136.9h6.6M209.5 138.9h-27.9v81.2h27.9"/>
<path d="M211.9 137.9h2.9M229.8 126.2v8.1M229.8 135.8v8.2M255.2 121.1l2.6 2.5h22.8M255.2 123.6l2.6 2.6h22.8M255.2 126.2l2.6 2.5h22.8M255.2 128.7l2.6 2.6h22.8M255.2 131.3l2.6 2.5h22.8M265.4 139.4h1.8M265.4 136.9h6.5M280.6 138.9h-30.4v81.2h27.9M283 137.9h2.9"/>
<path d="M298.4 126.2v8.1M298.4 135.8v8.2M400 123.1h3.8M52.1 151.6l2.5 2.5h20.3M52.1 154.1l2.5 2.6h20.3M54.6 159.7h5.8M92.1 154.1h158.1M92.1 156.7h89.5M92.1 159.2h20.9M97.8 152.1h6.5M97.8 157.2h6.5M97.8 154.6h6.5"/>
<path d="M107.9 144h33M110.5 141.4h30.4M128.2 141.9h6.7M143.3 143h3.4M143.3 140.5h3.1M176.5 144h33M179 141.4h30.5M196.8 141.9h2.4M211.9 143h3.4M211.9 140.5h3M245.1 144h35.5M247.6 141.4h33"/>
<path d="M265.4 141.9h2.4M283 143h3.4M283 140.5h3.1M16.5 173.7h3.8M32.5 160.6h5.8M41.9 161.7h31M67.3 177h7.6M74.9 174.4h-7.6v12.7M92.1 179.5h3.1M92.1 177h3.1M92.1 174.4h3.1M92.1 161.7h3.1"/>
<path d="M123.2 166.8l2.5 2.6h15.2M123.2 179.5l2.5 2.6h15.2M123.2 177l2.5 2.5h15.2M123.2 174.4l2.5 2.6h15.2M123.2 171.9l2.5 2.5h15.2M123.2 169.4l2.5 2.5h15.2M156.2 169.4h12.7l2.5 2.5M156.2 179.5h12.7l2.5 2.6M156.2 177h12.7l2.5 2.5M156.2 174.4h12.7l2.5 2.6M156.2 171.9h12.7l2.5 2.5M191.7 166.8l2.6 2.6h15.2"/>
<path d="M191.7 179.5l2.6 2.6h15.2M191.7 177l2.6 2.5h15.2M191.7 174.4l2.6 2.6h15.2M191.7 171.9l2.6 2.5h15.2M191.7 169.4l2.6 2.5h15.2M224.8 169.4h12.7l2.5 2.5M224.8 179.5h12.7l2.5 2.6M224.8 177h12.7l2.5 2.5M224.8 174.4h12.7l2.5 2.6M224.8 171.9h12.7l2.5 2.5M260.3 166.8l2.6 2.6h15.2M260.3 179.5l2.6 2.6h15.2"/>
<path d="M260.3 177l2.6 2.5h15.2M260.3 174.4l2.6 2.6h15.2M260.3 171.9l2.6 2.5h15.2M260.3 169.4l2.6 2.5h15.2M293.3 169.4h12.7l2.6 2.5M293.3 179.5h12.7l2.6 2.6M293.3 177h12.7l2.6 2.5M293.3 174.4h12.7l2.6 2.6M293.3 171.9h12.7l2.6 2.5M316.2 171.4v1M316.2 173.4v1.1M316.2 175.5v1"/>
<path d="M316.2 177.5v1.1M316.2 179.6v1M317.2 169.4h-1v1M318.2 169.4h1.1M320.3 169.4h1M322.3 169.4h1.1M324.4 169.4h1M326.3 179.5v10.2h7.7M326.4 169.4h1.1M328.5 169.4h1M330.5 169.4h1.1M332.5 169.4h1.1"/>
<path d="M334.6 169.4h1M336.6 169.4h1.1M338.7 169.4h1M340.7 169.4h1.1M342.8 169.4h1M344.8 169.4h1.1M346.9 169.4h1M348.9 169.4h1M350.9 169.4h1.1M353 169.4h1M355 169.4h1.1M357.1 169.4h1"/>
<path d="M359.1 169.4h1.1M361.2 169.4h1M363.2 169.4h1.1M365.3 169.4h1M367.3 169.4h1M369.4 169.4h1M371.4 169.4h1M373.4 169.4h1.1M375.5 169.4h1M377.5 169.4h1.1M379.6 169.4h1M381.6 169.4h1.1"/>
<path d="M383.7 169.4h1M385.7 169.4h1.1M387.8 169.4h1M389.8 169.4h1M391.8 169.4h1.1M393.9 169.4h1v1M394.9 171.4v1M394.9 173.4v1.1M394.9 175.5v1M394.9 177.5v1.1M394.9 179.6v1M400 173.7h3.8"/>
<path d="M67.3 182.1h5.6M92.1 182.1h3.1M118.1 199.8l2.5 2.6h20.3M123.2 182.1l2.5 2.5h15.2M123.2 192.2l2.5 2.6h15.2M123.2 184.6l2.5 2.5h15.2M123.2 187.1l2.5 2.6h15.2M123.2 189.7l2.5 2.5h15.2M123.2 194.8l2.5 2.5h15.2M123.2 197.3l2.5 2.5h15.2M156.2 184.6h12.7l2.5 2.5M156.2 187.1h12.7l2.5 2.6"/>
<path d="M156.2 182.1h12.7l2.5 2.5M186.7 199.8l2.5 2.6h20.3M191.7 182.1l2.6 2.5h15.2M191.7 192.2l2.6 2.6h15.2M191.7 184.6l2.6 2.5h15.2M191.7 187.1l2.6 2.6h15.2M191.7 189.7l2.6 2.5h15.2M191.7 194.8l2.6 2.5h15.2M191.7 197.3l2.6 2.5h15.2M224.8 184.6h12.7l2.5 2.5M224.8 187.1h12.7l2.5 2.6M224.8 182.1h12.7l2.5 2.5"/>
<path d="M255.2 199.8l2.6 2.6h20.3M260.3 182.1l2.6 2.5h15.2M260.3 192.2l2.6 2.6h15.2M260.3 184.6l2.6 2.5h15.2M260.3 187.1l2.6 2.6h15.2M260.3 189.7l2.6 2.5h15.2M260.3 194.8l2.6 2.5h15.2M260.3 197.3l2.6 2.5h15.2M293.3 184.6h12.7l2.6 2.5M293.3 187.1h12.7l2.6 2.6M293.3 182.1h12.7l2.6 2.5M316.2 181.6v1.1"/>
<path d="M316.2 183.7v1M316.2 185.7v1.1M316.2 187.8v1M316.2 189.8v1.1M316.2 191.9v1M316.2 193.9v1M316.2 196v1M316.2 198v1.1M317.3 195.3h6.5M317.3 197.8h6.5M321.5 192.7h2.3M322 190.2h1.8"/>
<path d="M325.1 194.8h8.9M325.1 192.2h8.9M325.1 197.3h8.9M325.1 199.8h8.9M326.3 184.6h7.7M326.3 187.1h7.7M351.2 184.6h18.3M351.2 194.8h5.6v30.4h12.7M351.2 187.1h13.2v7.7h5.1M351.2 189.7h10.7v15.2h7.6M351.2 192.2h8.2v22.9h10.1M351.2 197.3h3.1"/>
<path d="M351.2 199.8h3.1M374.6 184.6h15.2v48.2M374.6 194.8h15.2M383 186.6l1.4 1.4M383 196.8l1.4 1.4M383.5 187.6l.5-.5 .4 .9zM383.5 187.6h.7M383.6 197.7h.6M383.6 197.8h.6M383.6 187.5h.6M383.7 187.7h.6M383.7 197.6h.5"/>
<path d="M383.8 187.4h.3M383.8 197.5h.3M383.9 187.2h.1M383.9 198h.4M383.9 197.4h.1M384 187.8h.3M384 197.3l.4 .9-.9-.4zM384.1 186.5l1.4 1.4M384.1 196.7l1.4 1.4M384.2 198.1h.1M384.3 188h.1M384.6 187.5l.5-.5 .4 .9z"/>
<path d="M384.6 197.7l.5-.5 .4 .9zM384.7 187.5h.7M384.7 197.6h.6M384.8 187.4h.5M384.8 197.7h.6M384.8 197.5h.5M384.9 187.6h.5M384.9 187.2h.4M384.9 197.4h.3M385 187.1h.2M385.1 197.8h.3M385.1 197.3h.1"/>
<path d="M385.1 187.7h.4M385.4 198h.1M385.4 187.8h.1M394.9 181.6v1.1M394.9 183.7v1M394.9 185.7v1.1M394.9 187.8v1M394.9 189.8v1.1M394.9 191.9v1M394.9 193.9v1M394.9 196v1M394.9 198v1.1"/>
<path d="M118.1 202.4l2.5 2.5h20.3M118.1 212.5l2.5 2.6h20.3M118.1 204.9l2.5 2.6h20.3M118.1 207.5l2.5 2.5h20.3M118.1 210l2.5 2.5h20.3M128.2 218.1h6.6M143.3 219.2h3M161.3 207.5v8.1M161.3 217.1v8.1M186.7 202.4l2.5 2.5h20.3M186.7 212.5l2.5 2.6h20.3M186.7 204.9l2.5 2.6h20.3"/>
<path d="M186.7 207.5l2.5 2.5h20.3M186.7 210l2.5 2.5h20.3M196.8 218.1h6.6M211.9 219.2h2.9M229.8 207.5v8.1M229.8 217.1v8.1M255.2 202.4l2.6 2.5h20.3M255.2 212.5l2.6 2.6h20.3M255.2 204.9l2.6 2.6h20.3M255.2 207.5l2.6 2.5h20.3M255.2 210l2.6 2.5h20.3M265.4 218.1h6.5"/>
<path d="M280.4 219.2h3M298.4 207.5v8.1M298.4 217.1v8.1M316.2 200v1.1M316.2 202.1v1M316.2 204.1v1.1M316.2 206.2v1M316.2 208.2v1.1M316.2 210.3v1M316.2 212.3v1.1M316.2 214.4v1M316.2 216.4v1.1"/>
<path d="M316.2 218.5v1M317.3 200.4h6.5M325.1 202.4h8.9M326.3 210h5.7M332 207.5h-5.7v7.6M349.2 217.6v6.9M351.2 202.4h3.1M374.6 204.9h15.2M374.6 215.1h15.2M383 206.9l1.4 1.4M383 217.1l1.4 1.4M383.5 218.1l.9 .4"/>
<path d="M383.5 218.1h.7M383.6 208h.6M383.6 207.9h.6M383.6 218h.6M383.7 207.8h.4M383.7 217.9h.4M383.8 218.2h.5M383.8 207.6h.3M383.9 208.1h.4M383.9 217.8h.2M383.9 207.5h.1M384 217.6h.1"/>
<path d="M384 207.5l.4 .8-.9-.3zM384 217.6l-.5 .5M384 217.6l.4 .9M384.1 218.4h.2M384.1 206.8l1.4 1.4M384.1 208.2h.2M384.1 217l1.4 1.4M384.4 218.5h.1M384.6 207.8l.5-.5 .4 .9zM384.7 218h.7M384.7 207.9h.7M384.7 207.8h.6"/>
<path d="M384.7 217.9h.6M384.8 207.6h.5M384.9 217.8h.4M385 218.1h.4M385 207.5h.2M385 217.6h.2M385 208h.4M385.1 207.4h.1M385.1 217.5h.1M385.1 217.5l-.5 .5 .9 .4M385.1 217.5l.4 .9M385.2 218.2h.3"/>
<path d="M385.3 208.1h.2M385.5 218.4h.1M394.9 200v1.1M394.9 202.1v1M394.9 204.1v1.1M394.9 206.2v1M394.9 208.2v1.1M394.9 210.3v1M394.9 212.3v1.1M394.9 214.4v1M394.9 216.4v1.1M394.9 218.5v1"/>
<path d="M16.5 224.2h3.8M128.2 220.7h1.8M128.2 223.2h6.7M143.3 224.3h3.4M143.3 221.7h3.1M196.8 220.7h1.8M196.8 223.2h2.4M211.9 224.3h3.4M211.9 221.7h3M265.4 220.7h1.8M265.4 223.2h2.4M280.4 224.3h3.5"/>
<path d="M280.4 221.7h3.1M316.2 236.9v1h1M316.2 220.5v1.1M316.2 222.5v1.1M316.2 224.6v1M316.2 226.7v1M316.2 228.7v1M316.2 230.7v1.1M316.2 232.8v1M316.2 234.8v1.1M318.2 237.9h1.1M320.3 237.9h1"/>
<path d="M322.3 237.9h1.1M324.4 237.9h1M326.4 237.9h1.1M328.5 237.9h1M330.5 237.9h1.1M332.5 237.9h1.1M334.6 237.9h1M336.6 237.9h1.1M338.7 237.9h1M340.7 237.9h1.1M342.8 237.9h1M344.8 237.9h1.1"/>
<path d="M346.9 237.9h1M348.9 237.9h1M349.2 226v6.8M350.9 237.9h1.1M353 237.9h1M355 237.9h1.1M357.1 237.9h1M359.1 237.9h1.1M361.2 237.9h1M363.2 237.9h1.1M365.3 237.9h1M367.3 237.9h1"/>
<path d="M369.4 237.9h1M371.4 237.9h1M373.4 237.9h1.1M374.6 225.2h15.2M375.5 237.9h1M377.5 237.9h1.1M379.6 237.9h1M381.6 237.9h1.1M383 227.2l1.4 1.4M383.5 228.3l.9 .3M383.5 228.3h.7M383.6 228.1h.6"/>
<path d="M383.7 237.9h1M383.7 228.4h.6M383.8 228h.3M383.9 227.9h.2M384 227.8l-.5 .5M384 227.8l.4 .8M384 227.8h.1M384 228.5h.3M384.1 227.1l1.4 1.4M384.3 228.6h.1M384.6 228.1h.8M384.6 228.1l.9 .4"/>
<path d="M384.6 228.1l.5-.5 .4 .9M384.8 228h.5M384.9 228.3h.5M384.9 227.9h.4M385 227.8h.2M385.1 227.6h.1M385.2 228.4h.3M385.5 228.5h.1M385.7 237.9h1.1M387.8 237.9h1M389.8 237.9h1M391.8 237.9h1.1"/>
<path d="M394.9 220.5v1.1M394.9 222.5v1.1M394.9 224.6v1M394.9 226.7v1M394.9 228.7v1M394.9 230.7v1.1M394.9 232.8v1M394.9 234.8v1.1M394.9 236.9v1h-1M400 224.2h3.8M67.8 274.7v3.9M115.2 274.7v3.9"/>
<path d="M162.7 274.7v3.9M210.2 274.7v3.9M257.6 274.7v3.9M305.1 274.7v3.9M352.6 274.7v3.9M400 274.6h.1"/>
<circle cx="91.1" cy="156.7" r=".99"/>
<circle cx="91.1" cy="159.2" r=".99"/>
<circle cx="91.1" cy="154.1" r=".99"/>
<circle cx="73.9" cy="161.7" r=".99"/>
<circle cx="91.1" cy="161.7" r=".99"/>
<circle cx="91.1" cy="174.4" r=".99"/>
<circle cx="91.1" cy="179.5" r=".99"/>
<circle cx="91.1" cy="177" r=".99"/>
<circle cx="73.9" cy="182.1" r=".99"/>
<circle cx="91.1" cy="182.1" r=".99"/>
<circle cx="350.2" cy="199.8" r=".99"/>
<circle cx="350.2" cy="197.3" r=".99"/>
<circle cx="350.2" cy="184.6" r=".99"/>
<circle cx="350.2" cy="194.8" r=".99"/>
<circle cx="350.2" cy="192.2" r=".99"/>
<circle cx="350.2" cy="189.7" r=".99"/>
<circle cx="350.2" cy="187.1" r=".99"/>
<circle cx="333" cy="210" r=".99"/>
<circle cx="333" cy="207.5" r=".99"/>
<circle cx="350.2" cy="202.4" r=".99"/>
</g>
<g fill="none" stroke="#000" stroke-width=".25">
<path d="M35.1 68.8h5.3l1.5 1.5-1.5 1.5h-5.3zM35.7 63.7h4.7l1.5 1.5-1.5 1.6h-4.7zM99.1 79.8l1.2-1.9 1.3 1.9M383.5 100.1l1.3-1.8 1.2 1.8M160 128.1l1.3-1.9 1.2 1.9M228.6 128.1l1.2-1.9 1.3 1.9M297.1 128.1l1.3-1.9 1.3 1.9M337.1 121.1h3.9M159.4 144h3.8M227.9 144h3.9M296.5 144h3.8M31.6 160.2h8.8l1.5 1.5-1.5 1.6h-8.8z"/>
<path d="M65.4 187.1h3.8M325.1 181.4l1.2-1.9 1.3 1.9M369.5 183.7h5.1v1.8h-5.1zM369.5 193.9h5.1v1.7h-5.1zM382.2 183.7h.7M382.2 195.7h.7M382.2 193.9h.9M382.2 183.3l2.6 1.3-2.6 1.3zM382.2 193.5l2.6 1.3-2.6 1.2zM382.2 185.7h.4M382.2 185.4h.9M382.2 185.2h1.3"/>
<path d="M382.2 185h1.7M382.2 184.8h2.2M382.2 184.6h2.5M382.2 184.3h2.1M382.2 184.1h1.6M382.2 183.9h1.2M382.2 183.5h.3M382.2 195.9h.3M382.2 195.5h1.2M382.2 195.2h1.6M382.2 195h2.1M382.2 194.8h2.5"/>
<path d="M382.2 194.6h2.2M382.2 194.3h1.7M382.2 194.1h1.3M382.2 193.7h.4M384.8 183.3v2.6M384.8 193.5v2.5M160 209.4l1.3-1.9 1.2 1.9M228.6 209.4l1.2-1.9 1.3 1.9M297.1 209.4l1.3-1.9 1.3 1.9M324.4 215.1h3.9M347.9 219.5l1.3-1.9 1.3 1.9M369.5 204h5.1v1.8h-5.1z"/>
<path d="M369.5 214.2h5.1v1.8h-5.1zM382.2 203.6l2.6 1.3-2.6 1.3zM382.2 213.8l2.6 1.3-2.6 1.2zM382.2 206.1h.2M382.2 205.9h.6M382.2 205.7h1M382.2 205.4h1.5M382.2 205.2h1.9M382.2 205h2.4M382.2 204.8h2.3M382.2 204.6h1.9M382.2 204.3h1.4"/>
<path d="M382.2 204.1h1M382.2 203.9h.5M382.2 203.7h.1M382.2 216.1h.5M382.2 215.9h.9M382.2 215.7h1.4M382.2 215.5h1.8M382.2 215.2h2.3M382.2 215h2.4M382.2 214.8h2M382.2 214.6h1.6M382.2 214.3h1.1"/>
<path d="M382.2 214.1h.7M382.2 213.9h.2M384.8 203.6v2.6M384.8 213.8v2.5M159.4 225.2h3.8M227.9 225.2h3.9M296.5 225.2h3.8M347.3 232.8h3.8M369.5 224.3h5.1v1.8h-5.1zM382.2 223.9l2.6 1.3-2.6 1.3zM382.2 225.2h2.6M382.2 226.1h.8"/>
<path d="M382.2 224.3h.8M382.2 226.3h.3M382.2 225.9h1.2M382.2 225.7h1.7M382.2 225.4h2.1M382.2 225h2.1M382.2 224.8h1.7M382.2 224.6h1.2M382.2 224.1h.3M384.8 223.9v2.6M387.9 232.8h3.9M313.6 249.3h86.4"/>
<path d="M313.6 254.4h86.4M313.6 259.5h86.4M372.1 259.5v5.1M313.6 264.6h86.4M400 268.4v1.3h-86.4"/>
</g>
<path d="M20.3 22.1h379.7v252.6h-379.7zM140.9 85.6h15.3v60.9h-15.3zM209.5 85.6h15.3v60.9h-15.3zM280.6 85.6h15.3v60.9h-15.3zM74.9 151.6h15.3v12.7h-15.3zM74.9 171.9h15.3v12.7h-15.3zM140.9 166.8h15.3v61h-15.3zM209.5 166.8h15.3v61h-15.3zM278.1 166.8h15.2v61h-15.2zM334 182.1h15.2v30.4h-15.2zM313.6 244.3v30.4M400 244.3h-116.8v30.4" fill="none" stroke="#000" stroke-width=".61"/>
<path d="M16.5 18.2h387.3v260.4h-387.3z" fill="none" stroke="#000" stroke-width=".32"/>
<path d="M89.5 77.3h6.4v.6h-6.4zM90.2 75.4v1.3M92.7 75.4v1.3M95.2 75.4v1.3" fill="none" stroke="#000" stroke-width=".42"/>
<g fill="#000" stroke="#000" stroke-width=".21">
<path d="M337 108.9h4.1v.5h-4.1zM337 109.9h4.1v.5h-4.1zM344.6 108.9h4.1v.5h-4.1zM344.6 109.9h4.1v.5h-4.1zM352.3 108.9h4v.5h-4zM352.3 109.9h4v.5h-4zM359.9 108.9h4v.5h-4zM359.9 109.9h4v.5h-4zM367.5 108.9h4.1v.5h-4.1zM367.5 109.9h4.1v.5h-4.1zM375.1 108.9h4.1v.5h-4.1zM375.1 109.9h4.1v.5h-4.1z"/>
<path d="M382.7 108.9h4.1v.5h-4.1zM382.7 109.9h4.1v.5h-4.1zM159.2 135.3h4.1v.5h-4.1zM159.2 134.3h4.1v.5h-4.1zM227.8 135.3h4.1v.5h-4.1zM227.8 134.3h4.1v.5h-4.1zM296.4 135.3h4v.5h-4zM296.4 134.3h4v.5h-4zM384.5 183.1h.5v3h-.5zM384.5 193.2h.5v3.1h-.5zM159.2 216.6h4.1v.5h-4.1zM159.2 215.6h4.1v.5h-4.1z"/>
<path d="M227.8 216.6h4.1v.5h-4.1zM227.8 215.6h4.1v.5h-4.1zM296.4 216.6h4v.5h-4zM296.4 215.6h4v.5h-4zM384.5 203.4h.5v3h-.5zM384.5 213.6h.5v3h-.5zM347.2 224.5h4v.5h-4zM347.2 225.5h4v.5h-4zM384.5 223.7h.5v3h-.5z"/>
</g>
<path d="M41.9 44.9h208.3l10.1 10.2v142.2M41.9 52.5h208.3l5 5.1v154.9M47 52.5l5.1 5.1v96.5M113 44.9l10.2 10.2v142.2M113 52.5l5.1 5.1v154.9M181.6 44.9l10.1 10.2v142.2M181.6 52.5l5.1 5.1v154.9M171.4 90.6v142.2l-5.1 5.1M240 90.6v142.2l-5.1 5.1M308.6 90.6v142.2l-5.1 5.1h-261.6" fill="none" stroke="#000" stroke-width=".76"/>
<g fill="#000" stroke="#000" stroke-width=".21">
<circle cx="85.1" cy="70.3" r=".51"/>
<circle cx="110.5" cy="65.2" r=".51"/>
<circle cx="176.5" cy="70.3" r=".51"/>
<circle cx="179" cy="65.2" r=".51"/>
<circle cx="339" cy="116" r=".51"/>
<circle cx="346.7" cy="116" r=".51"/>
<circle cx="346.7" cy="103.3" r=".51"/>
<circle cx="354.3" cy="103.3" r=".51"/>
<circle cx="354.3" cy="116" r=".51"/>
<circle cx="361.9" cy="103.3" r=".51"/>
<circle cx="361.9" cy="116" r=".51"/>
<circle cx="369.5" cy="116" r=".51"/>
<circle cx="369.5" cy="103.3" r=".51"/>
<circle cx="377.1" cy="103.3" r=".51"/>
<circle cx="377.1" cy="116" r=".51"/>
<circle cx="384.8" cy="103.3" r=".51"/>
<circle cx="107.9" cy="144" r=".51"/>
<circle cx="110.5" cy="141.4" r=".51"/>
<circle cx="113" cy="159.2" r=".51"/>
<circle cx="176.5" cy="144" r=".51"/>
<circle cx="179" cy="141.4" r=".51"/>
<circle cx="181.6" cy="156.7" r=".51"/>
<circle cx="245.1" cy="144" r=".51"/>
<circle cx="247.6" cy="141.4" r=".51"/>
<circle cx="250.2" cy="154.1" r=".51"/>
<circle cx="67.3" cy="177" r=".51"/>
<circle cx="67.3" cy="182.1" r=".51"/>
<circle cx="326.3" cy="184.6" r=".51"/>
<circle cx="326.3" cy="187.1" r=".51"/>
<circle cx="389.8" cy="194.8" r=".51"/>
<circle cx="326.3" cy="210" r=".51"/>
<circle cx="389.8" cy="215.1" r=".51"/>
<circle cx="389.8" cy="204.9" r=".51"/>
<circle cx="389.8" cy="225.2" r=".51"/>
</g>
<use href="#words"/>
</svg>
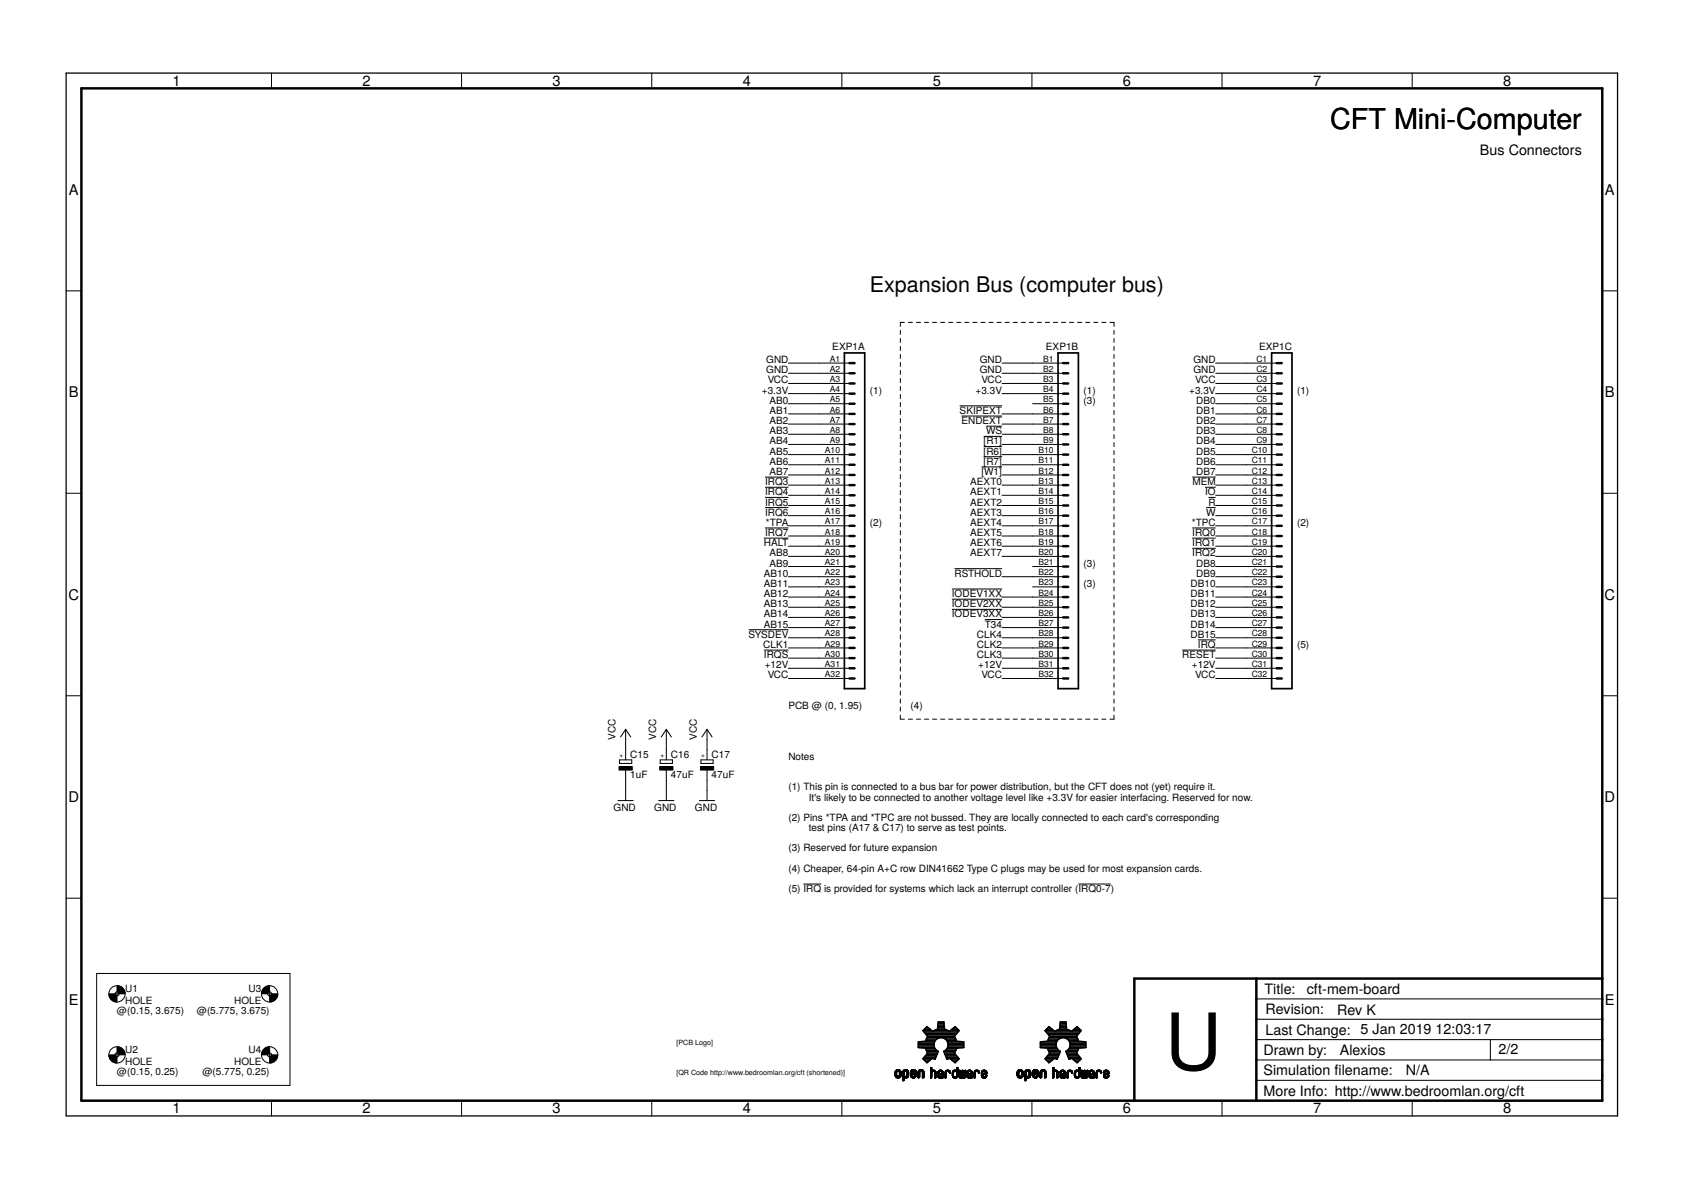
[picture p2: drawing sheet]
<svg xmlns="http://www.w3.org/2000/svg" width="420mm" height="297mm" viewBox="0 0 420 297" stroke-linecap="round" stroke-linejoin="round" font-family="sans-serif">
<defs><g id="words">
<text font-size="19.7" x="290.8" y="267.1">U</text>
<text font-size="7.2" x="332.1" y="32.2">CFT Mini-Computer</text>
<text font-size="5.4" x="217.1" y="72.8">Expansion Bus (computer bus)</text>
<g font-size="3.7">
<text x="43" y="21.4">1</text>
<text x="90.5" y="21.4">2</text>
<text x="138" y="21.4">3</text>
<text x="185.4" y="21.4">4</text>
<text x="232.9" y="21.4">5</text>
<text x="280.3" y="21.4">6</text>
<text x="327.8" y="21.4">7</text>
<text x="375.3" y="21.4">8</text>
<text x="17.2" y="48.6">A</text>
<text x="400.7" y="48.6">A</text>
<text x="17.2" y="99.2">B</text>
<text x="400.7" y="99.2">B</text>
<text x="17.1" y="149.7">C</text>
<text x="400.6" y="149.7">C</text>
<text x="17.1" y="200.2">D</text>
<text x="400.6" y="200.2">D</text>
<text x="17.2" y="250.8">E</text>
<text x="400.7" y="250.8">E</text>
<text x="43" y="277.9">1</text>
<text x="90.5" y="277.9">2</text>
<text x="138" y="277.9">3</text>
<text x="185.4" y="277.9">4</text>
<text x="232.9" y="277.9">5</text>
<text x="280.3" y="277.9">6</text>
<text x="327.8" y="277.9">7</text>
<text x="375.3" y="277.9">8</text>
</g>
<g font-size="3.6">
<text x="369.5" y="38.6">Bus Connectors</text>
<text x="315.7" y="248.1">Title:</text>
<text x="326.2" y="248.2">cft-mem-board</text>
<text x="315.9" y="253.2">Revision:</text>
<text x="333.8" y="253.3">Rev K</text>
<text x="315.4" y="263.3">Drawn by:</text>
<text x="315.9" y="258.2">Last Change: 5 Jan 2019</text>
<text x="334.5" y="263.3">Alexios</text>
<text x="358.4" y="258.1">12:03:17</text>
<text x="374.1" y="263.2">2/2</text>
<text x="315.4" y="268.4">Simulation flename:</text>
<text x="333.2" y="268.4">i</text>
<text x="351" y="268.4">N/A</text>
<text x="315.4" y="273.5">More Info: http://www.bedroomlan.org/cft</text>
</g>
<g font-size="2.5">
<text x="207.8" y="87.3">EXP1A</text>
<text x="261.1" y="87.3">EXP1B</text>
<text x="314.3" y="87.3">EXP1C</text>
<text x="191.3" y="93.2">GND</text>
<text x="191.3" y="90.6">GND</text>
<text x="191.7" y="95.7">VCC</text>
<text x="244.6" y="93.2">GND</text>
<text x="244.6" y="90.6">GND</text>
<text x="245" y="95.7">VCC</text>
<text x="298" y="93.2">GND</text>
<text x="298" y="90.6">GND</text>
<text x="298.3" y="95.7">VCC</text>
<text x="190.2" y="98.2">+3.3V</text>
<text x="192.1" y="100.8">AB0</text>
<text x="217.1" y="98.2">(1)</text>
<text x="243.5" y="98.2">+3.3V</text>
<text x="270.5" y="98.2">(1)</text>
<text x="270.5" y="100.8">(3)</text>
<text x="296.9" y="98.2">+3.3V</text>
<text x="298.6" y="100.8">DB0</text>
<text x="323.8" y="98.2">(1)</text>
<text x="192.1" y="105.9">AB2</text>
<text x="192.1" y="103.3">AB1</text>
<text x="239.6" y="103.3">SKIPEXT</text>
<text x="240" y="105.9">ENDEXT</text>
<text x="298.6" y="105.9">DB2</text>
<text x="298.6" y="103.3">DB1</text>
<text x="192.1" y="113.5">AB5</text>
<text x="192.1" y="110.9">AB4</text>
<text x="192.1" y="108.4">AB3</text>
<text x="245.6" y="110.9">[R1]</text>
<text x="245.6" y="113.5">[R6]</text>
<text x="246.2" y="108.4">WS</text>
<text x="298.6" y="113.5">DB5</text>
<text x="298.6" y="110.9">DB4</text>
<text x="298.6" y="108.4">DB3</text>
<text x="192.1" y="118.6">AB7</text>
<text x="192.1" y="116">AB6</text>
<text x="245" y="118.6">[W1]</text>
<text x="245.6" y="116">[R7]</text>
<text x="298.6" y="118.6">DB7</text>
<text x="298.6" y="116">DB6</text>
<text x="191" y="121.1">IRQ3</text>
<text x="191" y="123.6">IRQ4</text>
<text x="242.2" y="123.6">AEXT1</text>
<text x="242.2" y="121.1">AEXT0</text>
<text x="297.7" y="121.1">MEM</text>
<text x="300.9" y="123.6">IO</text>
<text x="191" y="126.2">IRQ5</text>
<text x="191" y="128.7">IRQ6</text>
<text x="191.2" y="131.3">*TPA</text>
<text x="217.1" y="131.3">(2)</text>
<text x="242.2" y="131.3">AEXT4</text>
<text x="242.2" y="128.7">AEXT3</text>
<text x="242.2" y="126.2">AEXT2</text>
<text x="297.5" y="131.3">*TPC</text>
<text x="301.1" y="128.7">W</text>
<text x="301.7" y="126.2">R</text>
<text x="323.8" y="131.3">(2)</text>
<text x="190.7" y="136.3">HALT</text>
<text x="191" y="133.8">IRQ7</text>
<text x="242.2" y="136.3">AEXT6</text>
<text x="242.2" y="133.8">AEXT5</text>
<text x="297.7" y="133.8">IRQ0</text>
<text x="297.7" y="136.3">IRQ1</text>
<text x="190.7" y="144">AB10</text>
<text x="192.1" y="141.4">AB9</text>
<text x="192.1" y="138.9">AB8</text>
<text x="238.3" y="144">RSTHOLD</text>
<text x="242.2" y="138.9">AEXT7</text>
<text x="270.5" y="141.4">(3)</text>
<text x="297.7" y="138.9">IRQ2</text>
<text x="298.6" y="144">DB9</text>
<text x="298.6" y="141.4">DB8</text>
<text x="190.7" y="149">AB12</text>
<text x="190.7" y="146.5">AB11</text>
<text x="237.6" y="149">IODEV1XX</text>
<text x="270.5" y="146.5">(3)</text>
<text x="297.2" y="149">DB11</text>
<text x="297.2" y="146.5">DB10</text>
<text x="190.7" y="154.1">AB14</text>
<text x="190.7" y="151.6">AB13</text>
<text x="237.6" y="154.1">IODEV3XX</text>
<text x="237.6" y="151.6">IODEV2XX</text>
<text x="297.2" y="154.1">DB13</text>
<text x="297.2" y="151.6">DB12</text>
<text x="186.9" y="159.2">SYSDEV</text>
<text x="190.6" y="161.7">CLK1</text>
<text x="190.7" y="156.7">AB15</text>
<text x="243.9" y="161.7">CLK2</text>
<text x="243.9" y="159.2">CLK4</text>
<text x="245.8" y="156.7">T34</text>
<text x="297.2" y="159.2">DB15</text>
<text x="297.2" y="156.7">DB14</text>
<text x="299.1" y="161.7">IRQ</text>
<text x="323.8" y="161.7">(5)</text>
<text x="190.7" y="164.3">IRQS</text>
<text x="190.9" y="166.8">+12V</text>
<text x="243.9" y="164.3">CLK3</text>
<text x="244.2" y="166.8">+12V</text>
<text x="295.2" y="164.3">RESET</text>
<text x="297.6" y="166.8">+12V</text>
<text x="191.7" y="169.4">VCC</text>
<text x="245" y="169.4">VCC</text>
<text x="298.3" y="169.4">VCC</text>
<text x="196.8" y="177">PCB @ (0, 1.95)</text>
<text x="227.3" y="177">(4)</text>
<text x="153.7" y="184.6" transform="rotate(-90 153.7 184.6)">VCC</text>
<text x="163.8" y="184.6" transform="rotate(-90 163.8 184.6)">VCC</text>
<text x="174" y="184.6" transform="rotate(-90 174 184.6)">VCC</text>
<text x="157.3" y="189.2">C15</text>
<text x="167.5" y="189.2">C16</text>
<text x="177.7" y="189.2">C17</text>
<text x="196.8" y="189.7">Notes</text>
<text x="157.3" y="194.3">1uF</text>
<text x="167.5" y="194.3">47uF</text>
<text x="177.7" y="194.3">47uF</text>
<text x="196.8" y="197.3">(1) This pin is connected to a bus bar for power distribution, but the CFT does not (yet) require it.</text>
<text x="153.2" y="202.4">GND</text>
<text x="163.3" y="202.4">GND</text>
<text x="173.5" y="202.4">GND</text>
<text x="201.9" y="199.8">It's likely to be connected to another voltage level like +3.3V for easier interfacing. Reserved for now.</text>
<text x="196.8" y="204.9">(2) Pins *TPA and *TPC are not bussed. They are locally connected to each card's corresponding</text>
<text x="201.9" y="207.4">test pins (A17 &amp; C17) to serve as test points.</text>
<text x="196.8" y="212.5">(3) Reserved for future expansion</text>
<text x="196.8" y="217.6">(4) Cheaper, 64-pin A+C row DIN41662 Type C plugs may be used for most expansion cards.</text>
<text x="196.8" y="222.7">(5) IRQ is provided for systems which lack an interrupt controller (IRQ0-7)</text>
<text x="31.2" y="250.5">HOLE</text>
<text x="31.2" y="247.5">U1</text>
<text x="58.5" y="250.5">HOLE</text>
<text x="62.1" y="247.5">U3</text>
<text x="29.2" y="253.2">@(0.15, 3.675)</text>
<text x="49.1" y="253.2">@(5.775, 3.675)</text>
<text x="31.2" y="262.7">U2</text>
<text x="62.1" y="262.7">U4</text>
<text x="29.2" y="268.4">@(0.15, 0.25)</text>
<text x="31.2" y="265.8">HOLE</text>
<text x="50.5" y="268.4">@(5.775, 0.25)</text>
<text x="58.5" y="265.8">HOLE</text>
</g>
<g font-size="2.1">
<text x="207.1" y="90.3">A1</text>
<text x="207.1" y="92.8">A2</text>
<text x="207.1" y="95.4">A3</text>
<text x="260.5" y="90.3">B1</text>
<text x="260.5" y="92.8">B2</text>
<text x="260.5" y="95.4">B3</text>
<text x="313.7" y="90.3">C1</text>
<text x="313.7" y="92.8">C2</text>
<text x="313.7" y="95.4">C3</text>
<text x="207.1" y="97.9">A4</text>
<text x="207.1" y="100.4">A5</text>
<text x="260.5" y="97.9">B4</text>
<text x="260.5" y="100.4">B5</text>
<text x="313.7" y="97.9">C4</text>
<text x="313.7" y="100.4">C5</text>
<text x="207.1" y="103">A6</text>
<text x="207.1" y="105.5">A7</text>
<text x="260.5" y="103">B6</text>
<text x="260.5" y="105.5">B7</text>
<text x="313.7" y="103">C6</text>
<text x="313.7" y="105.5">C7</text>
<text x="205.9" y="113.1">A10</text>
<text x="207.1" y="108">A8</text>
<text x="207.1" y="110.6">A9</text>
<text x="259.3" y="113.1">B10</text>
<text x="260.5" y="108">B8</text>
<text x="260.5" y="110.6">B9</text>
<text x="312.5" y="113.1">C10</text>
<text x="313.7" y="108">C8</text>
<text x="313.7" y="110.6">C9</text>
<text x="205.9" y="115.7">A11</text>
<text x="205.9" y="118.2">A12</text>
<text x="259.3" y="115.7">B11</text>
<text x="259.3" y="118.2">B12</text>
<text x="312.5" y="115.7">C11</text>
<text x="312.5" y="118.2">C12</text>
<text x="205.9" y="120.7">A13</text>
<text x="205.9" y="123.3">A14</text>
<text x="205.9" y="125.8">A15</text>
<text x="259.3" y="120.7">B13</text>
<text x="259.3" y="123.3">B14</text>
<text x="259.3" y="125.8">B15</text>
<text x="312.5" y="120.7">C13</text>
<text x="312.5" y="123.3">C14</text>
<text x="312.5" y="125.8">C15</text>
<text x="205.9" y="128.4">A16</text>
<text x="205.9" y="130.9">A17</text>
<text x="259.3" y="128.4">B16</text>
<text x="259.3" y="130.9">B17</text>
<text x="312.5" y="128.4">C16</text>
<text x="312.5" y="130.9">C17</text>
<text x="205.9" y="133.4">A18</text>
<text x="205.9" y="136">A19</text>
<text x="259.3" y="133.4">B18</text>
<text x="259.3" y="136">B19</text>
<text x="312.5" y="133.4">C18</text>
<text x="312.5" y="136">C19</text>
<text x="205.9" y="138.5">A20</text>
<text x="205.9" y="141.1">A21</text>
<text x="205.9" y="143.6">A22</text>
<text x="259.3" y="138.5">B20</text>
<text x="259.3" y="141.1">B21</text>
<text x="259.3" y="143.6">B22</text>
<text x="312.5" y="138.5">C20</text>
<text x="312.5" y="141.1">C21</text>
<text x="312.5" y="143.6">C22</text>
<text x="205.9" y="146.1">A23</text>
<text x="205.9" y="148.7">A24</text>
<text x="259.3" y="146.1">B23</text>
<text x="259.3" y="148.7">B24</text>
<text x="312.5" y="146.1">C23</text>
<text x="312.5" y="148.7">C24</text>
<text x="205.9" y="151.2">A25</text>
<text x="205.9" y="153.8">A26</text>
<text x="259.3" y="151.2">B25</text>
<text x="259.3" y="153.8">B26</text>
<text x="312.5" y="151.2">C25</text>
<text x="312.5" y="153.8">C26</text>
<text x="205.9" y="156.3">A27</text>
<text x="205.9" y="158.8">A28</text>
<text x="205.9" y="161.4">A29</text>
<text x="259.3" y="156.3">B27</text>
<text x="259.3" y="158.8">B28</text>
<text x="259.3" y="161.4">B29</text>
<text x="312.5" y="156.3">C27</text>
<text x="312.5" y="158.8">C28</text>
<text x="312.5" y="161.4">C29</text>
<text x="205.9" y="163.9">A30</text>
<text x="205.9" y="166.5">A31</text>
<text x="259.3" y="163.9">B30</text>
<text x="259.3" y="166.5">B31</text>
<text x="312.5" y="163.9">C30</text>
<text x="312.5" y="166.5">C31</text>
<text x="205.9" y="169">A32</text>
<text x="259.3" y="169">B32</text>
<text x="312.5" y="169">C32</text>
</g>
<g font-size="1.8">
<text x="155.6" y="189.3" transform="rotate(-90 155.6 189.3)">+</text>
<text x="165.8" y="189.3" transform="rotate(-90 165.8 189.3)">+</text>
<text x="175.9" y="189.3" transform="rotate(-90 175.9 189.3)">+</text>
<text x="168.9" y="260.8">[PCB Logo]</text>
<text x="168.9" y="268.4">[QR Code http://www.bedroomlan.org/cft (shortened)]</text>
</g>
</g></defs>
<g fill="none" stroke="#000" stroke-width=".25">
<path d="M67.8 18.2v3.9M115.2 18.2v3.9M162.7 18.2v3.9M210.2 18.2v3.9M257.6 18.2v3.9M305.1 18.2v3.9M352.6 18.2v3.9M20.3 22.1h379.7v252.6h-379.7zM16.5 72.6h3.8M400 72.6h3.8M196.8 90.6h15.3M196.8 93.2h15.3"/>
<path d="M196.8 95.7h15.3M196.8 98.3h15.3M224.8 82.5v1M224.8 84.5v1M224.8 86.5v1M224.8 88.5v1M224.8 90.5v1M224.8 92.5v1M224.8 94.5v1M224.8 96.5v1M224.8 98.5v1M225.8 80.5h-1v1"/>
<path d="M226.8 80.5h1M228.8 80.5h1M230.8 80.5h1M232.8 80.5h1M234.8 80.5h1M236.8 80.5h1M238.8 80.5h1.1M240.9 80.5h1M242.9 80.5h1M244.9 80.5h1M246.9 80.5h1M248.9 80.5h1"/>
<path d="M250.2 90.6h15.2M250.2 93.2h15.2M250.2 95.7h15.2M250.2 98.3h15.2M250.9 80.5h1M252.9 80.5h1.1M255 80.5h1M257 80.5h1M259 80.5h1M261 80.5h1M263 80.5h1M265 80.5h1"/>
<path d="M267 80.5h1M269 80.5h1M271 80.5h1.1M273.1 80.5h1M275.1 80.5h1M277.1 80.5h1v1M278.1 82.5v1M278.1 84.5v1M278.1 86.5v1M278.1 88.5v1M278.1 90.5v1M278.1 92.5v1"/>
<path d="M278.1 94.5v1M278.1 96.5v1M278.1 98.5v1M303.5 90.6h15.2M303.5 93.2h15.2M303.5 95.7h15.2M303.5 98.3h15.2M191 119.1h5.8M196.8 100.8h15.3M196.8 103.3h15.3M196.8 105.9h15.3M196.8 108.4h15.3"/>
<path d="M196.8 110.9h15.3M196.8 113.5h15.3M196.8 116h15.3M196.8 118.6h15.3M224.8 100.5v1M224.8 102.5v1M224.8 104.5v1M224.8 106.5v1M224.8 108.5v1M224.8 110.5v1M224.8 112.5v1M224.8 114.5v1"/>
<path d="M224.8 116.5v1M224.8 118.5v1M239.6 101.3h10.6M240 103.8h10.2M245 116.5h5.2M245.6 108.9h4.6M245.6 111.5h4.6M245.6 114h4.6M246.2 106.4h4M250.2 103.3h15.2M250.2 105.9h15.2M250.2 108.4h15.2"/>
<path d="M250.2 110.9h15.2M250.2 113.5h15.2M250.2 116h15.2M250.2 118.6h15.2M257.8 100.8h7.6M278.1 100.5v1M278.1 102.5v1M278.1 104.5v1M278.1 106.5v1M278.1 108.5v1M278.1 110.5v1M278.1 112.5v1"/>
<path d="M278.1 114.5v1M278.1 116.5v1M278.1 118.5v1M297.7 119.1h5.8M303.5 100.8h15.2M303.5 103.3h15.2M303.5 105.9h15.2M303.5 108.4h15.2M303.5 110.9h15.2M303.5 113.5h15.2M303.5 116h15.2M303.5 118.6h15.2"/>
<path d="M16.5 123.1h3.8M190.7 134.3h6.1M191 121.6h5.8M191 124.2h5.8M191 126.7h5.8M191 131.8h5.8M196.8 121.1h15.3M196.8 123.6h15.3M196.8 126.2h15.3M196.8 128.7h15.3M196.8 131.3h15.3M196.8 133.8h15.3"/>
<path d="M196.8 136.3h15.3M196.8 138.9h15.3M224.8 120.5v1M224.8 122.5v1M224.8 124.5v1M224.8 126.5v1M224.8 128.5v1M224.8 130.5v1M224.8 132.5v1M224.8 134.5v1M224.8 136.5v1M224.8 138.5v1"/>
<path d="M250.2 121.1h15.2M250.2 123.6h15.2M250.2 126.2h15.2M250.2 128.7h15.2M250.2 131.3h15.2M250.2 133.8h15.2M250.2 136.3h15.2M250.2 138.9h15.2M278.1 120.5v1M278.1 122.5v1M278.1 124.5v1M278.1 126.5v1"/>
<path d="M278.1 128.5v1M278.1 130.5v1M278.1 132.5v1M278.1 134.5v1M278.1 136.5v1M278.1 138.5v1M297.6 134.3h5.9M297.6 131.8h5.9M297.6 136.9h5.9M300.8 121.6h2.7M301.1 126.7h2.4M301.7 124.2h1.8"/>
<path d="M303.5 121.1h15.2M303.5 123.6h15.2M303.5 126.2h15.2M303.5 128.7h15.2M303.5 131.3h15.2M303.5 133.8h15.2M303.5 136.3h15.2M303.5 138.9h15.2M400 123.1h3.8M186.9 157.2h9.9M196.8 141.4h15.3M196.8 144h15.3"/>
<path d="M196.8 146.5h15.3M196.8 149h15.3M196.8 151.6h15.3M196.8 154.1h15.3M196.8 156.7h15.3M196.8 159.2h15.3M224.8 140.5v1M224.8 142.5v1M224.8 144.5v1M224.8 146.5v1M224.8 148.5v1M224.8 150.5v1"/>
<path d="M224.8 152.5v1M224.8 154.5v1M224.8 156.5v1M224.8 158.5v1M237.6 152.1h12.6M237.6 149.6h12.6M237.6 147h12.6M238.3 141.9h11.9M245.9 154.6h4.3M250.2 144h15.2M250.2 149h15.2M250.2 151.6h15.2"/>
<path d="M250.2 154.1h15.2M250.2 156.7h15.2M250.2 159.2h15.2M257.8 141.4h7.6M257.8 146.5h7.6M278.1 140.5v1M278.1 142.5v1M278.1 144.5v1M278.1 146.5v1M278.1 148.5v1M278.1 150.5v1M278.1 152.5v1"/>
<path d="M278.1 154.5v1M278.1 156.5v1M278.1 158.5v1M299 159.7h4.5M303.5 141.4h15.2M303.5 144h15.2M303.5 146.5h15.2M303.5 149h15.2M303.5 151.6h15.2M303.5 154.1h15.2M303.5 156.7h15.2M303.5 159.2h15.2"/>
<path d="M16.5 173.7h3.8M190.7 162.3h6.1M196.8 161.7h15.3M196.8 164.3h15.3M196.8 166.8h15.3M196.8 169.4h15.3M224.8 160.5v1M224.8 162.5v1M224.8 164.5v1M224.8 166.5v1M224.8 168.5v1M224.8 170.5v1"/>
<path d="M224.8 172.5v1M224.8 174.5v1M224.8 176.5v1M224.8 178.5v1h1M226.8 179.5h1M228.8 179.5h1M230.8 179.5h1M232.8 179.5h1M234.8 179.5h1M236.8 179.5h1M238.8 179.5h1.1M240.9 179.5h1"/>
<path d="M242.9 179.5h1M244.9 179.5h1M246.9 179.5h1M248.9 179.5h1M250.2 161.7h15.2M250.2 164.3h15.2M250.2 166.8h15.2M250.2 169.4h15.2M250.9 179.5h1M252.9 179.5h1.1M255 179.5h1M257 179.5h1"/>
<path d="M259 179.5h1M261 179.5h1M263 179.5h1M265 179.5h1M267 179.5h1M269 179.5h1M271 179.5h1.1M273.1 179.5h1M275.1 179.5h1M278.1 178.5v1h-1M278.1 160.5v1M278.1 162.5v1"/>
<path d="M278.1 164.5v1M278.1 166.5v1M278.1 168.5v1M278.1 170.5v1M278.1 172.5v1M278.1 174.5v1M278.1 176.5v1M295.1 162.3h8.4M303.5 161.7h15.2M303.5 164.3h15.2M303.5 166.8h15.2M303.5 169.4h15.2"/>
<path d="M400 173.7h3.8M154.3 199.8h3.8M154.7 189.7h3v.9h-3zM156.2 182.1v7.6M156.2 192.2v7.6M156.2 182.1l1.3 1.9M156.2 182.1l-1.3 1.9M164.4 199.8h3.9M164.8 189.7h3.1v.9h-3.1zM166.3 182.1v7.6M166.3 192.2v7.6M166.3 182.1l1.3 1.9"/>
<path d="M166.3 182.1l-1.2 1.9M174.6 199.8h3.8M175 189.7h3v.9h-3zM176.5 182.1v7.6M176.5 192.2v7.6M176.5 182.1l1.3 1.9M176.5 182.1l-1.3 1.9M16.5 224.2h3.8M200.6 220.7h4.4M269.2 220.7h8.1M400 224.2h3.8M24.1 243h48.3v27.9h-48.3z"/>
<path d="M28.7 248.1h1M29.2 247.6v1M66.8 248.1h1M67.3 247.6v1M313.6 249.3h86.4M313.6 254.4h86.4M313.6 259.5h86.4M372.1 259.5v5.1M28.7 263.3h1M29.2 262.8v1M66.8 263.3h1M67.3 262.8v1"/>
<path d="M67.8 274.7v3.9M115.2 274.7v3.9M162.7 274.7v3.9M210.2 274.7v3.9M223.5 268.4l.4 .1M223.5 268.4h.3M223.5 268.3h.3M223.5 268.2h.3M223.5 268.1h.3M223.5 268h.3M223.5 267.9h.3M223.5 267.8h.3"/>
<path d="M223.5 267.7h.3M223.5 268.5h.4M223.5 268.6h.5M223.5 268.5l.5 .1M223.5 268.7h1.4M223.6 268.7h1.2M223.6 267.3h1.2M223.6 268.8h1.2M223.6 268.9h1.1M223.6 267.2h1.1M223.7 267.1h1M223.8 267.1h.8"/>
<path d="M223.8 269h.8M223.9 269h.6M223.9 267.6l-.4 .1M223.9 267.5l-.4 .1M223.9 267.5h-.4M223.9 267h.6M224 267.4l-.5 .1M224.1 269.1h.2M224.3 268.6h.6M224.4 267.4h.5M224.5 267.5h.4M224.5 268.5h.4"/>
<path d="M224.5 267.6h.4M224.5 268.4h.4M224.5 268.3h.4M224.5 268.2h.4M224.5 268.1h.4M224.5 268h.4M224.5 267.9h.4M224.5 267.8h.4M224.5 267.7h.4M224.7 268.9h-1M224.9 267.4h-1.4M224.9 268.6h-.4"/>
<path d="M225.4 269.7h.2M225.4 269.5h.4M225.4 269.4h.4M225.4 269.3h.4M225.4 269.2h.4M225.4 269.1h.4M225.4 268.7h1.4M225.4 268.6h.6M225.4 268.5l.4 .1M225.4 268.5h.4M225.4 268.4h.4M225.4 268.3h.4"/>
<path d="M225.4 268.2h.4M225.4 268.1h.4M225.4 268h.4M225.4 267.9h.4M225.4 267.8h.4M225.4 267.7h.4M225.4 269.8h.1M225.5 267.3h1.3M225.5 267.2h1.2M225.6 267.2h1.1M225.6 267.1h1M225.7 267.1h.8"/>
<path d="M225.7 269.7h-.3M225.8 269.6h-.4M225.8 267.6h-.4M225.8 267.5l-.4 .1M225.9 267.5h-.5M225.9 267h.5M225.9 267.4h-.5M226 269.1h.3M226.3 268.6h.5M226.3 267.4h.5M226.4 267.5h.4M226.4 267.5l.4 .1"/>
<path d="M226.4 269l-1 .1M226.4 268.4h.4M226.4 267.7h.4M226.4 267.6h.4M226.5 268.4h.3M226.5 268.3h.3M226.5 268.2h.3M226.5 268.1h.3M226.5 268h.3M226.5 267.9h.3M226.5 267.8h.3M226.5 267.7h.3"/>
<path d="M226.5 269h-1.1M226.6 268.9l-1.2 .1M226.7 268.9h-1.3M226.7 268.8h-1.3M226.8 268.7l-1.4 .1M226.8 267.4h-1.4M226.8 268.6h-.4M226.8 268.5h-.4M227.3 268.6h.6M227.3 268.5l.5 .1M227.3 268.5h.4M227.3 268.4l.4 .1"/>
<path d="M227.3 267.9h1.4M227.3 267.8l.4 .1M227.3 267.8h.3M227.3 267.7h.4M227.3 267.5h.4M227.4 268.7h1.3M227.4 268.7h1.2M227.4 267.3h1.3M227.4 268.8h1.2M227.4 267.3h1.2M227.5 268.9h1.1M227.5 267.2h1.1"/>
<path d="M227.5 268.9h1M227.6 267.1h.9M227.6 269h.8M227.6 267.1h.8M227.7 269h.7M227.7 267.7h-.4M227.7 267.6h-.4M227.8 267h.5M227.8 268.4h-.5M227.8 267.5h-.5M227.8 267.9h.9M227.9 267.4l-.6 .1"/>
<path d="M227.9 269.1h.3M227.9 268.3h-.6M228 267.8h.7M228 268.2l-.7 .1M228.1 267.8h.6M228.2 268.2h-.9M228.2 267.7h.5M228.2 267.4h.5M228.3 267.5h.4M228.3 268.6h.4M228.3 268.5h.4M228.3 268.1h-1"/>
<path d="M228.3 267.6h.4M228.3 268.4h.4M228.4 268.4h.3M228.4 268.3h.3M228.5 268.3h.2M228.5 268l-1.2 .1M228.6 268.2h.1M228.6 268h-1.3M228.7 267.4h-1.3M228.7 268.6h-.5M229.2 268.9h.4M229.2 268.8h.4"/>
<path d="M229.2 268.7h.4M229.2 268.6h.4M229.2 268.5h.4M229.2 268.4h.4M229.2 268.3h.4M229.2 268.2h.4M229.2 268.1h.4M229.2 268h.4M229.2 267.9h.4M229.2 267.8h.4M229.2 267.7h.4M229.2 267.6h.4"/>
<path d="M229.2 269h.2M229.3 267.3h1.3M229.3 267.3h1.2M229.4 267.2h1.1M229.4 267.1h1M229.5 269h-.3M229.5 267.1h.8M229.6 268.9l-.4 .1M229.6 267.5l-.4 .1M229.7 267.5h-.5M229.7 267h.5M229.8 267.4l-.6 .1"/>
<path d="M230.1 267.4l.5 .1M230.2 267.5h.5M230.3 268.9h.4M230.3 268.8h.4M230.3 268.7h.4M230.3 268.6h.4M230.3 268.5h.4M230.3 268.4h.4M230.3 268.3h.4M230.3 268.2h.4M230.3 268.1h.4M230.3 268h.4"/>
<path d="M230.3 267.9h.4M230.3 267.8h.4M230.3 267.7h.4M230.3 267.6h.4M230.5 269h-.2M230.6 269h-.3M230.6 267.4h-1.3M230.7 268.9l-.4 .1M232.3 266.6h.3M232.3 269.1h.1M232.3 268.9h.3M232.3 268.8h.3"/>
<path d="M232.3 268.7h.3M232.3 268.6h.3M232.3 268.5h.3M232.3 268.4h.3M232.3 268.3h.3M232.3 268.2h.3M232.3 268.1h.3M232.3 268h.3M232.3 267.9h.3M232.3 267.8h.3M232.3 267.7h.3M232.3 267.3h1.2"/>
<path d="M232.3 267.2l1.1 .1M232.3 267.2h1.1M232.3 267.1h.3M232.3 267h.3M232.3 266.9h.3M232.3 266.8h.3M232.3 266.7h.3M232.3 266.5h.3M232.4 266.5h.2M232.6 269l-.3 .1M232.6 269h-.3M232.6 267.7l-.3 .1"/>
<path d="M232.6 267.6h-.3M232.7 267.5l-.4 .1M232.7 267.5h-.4M232.7 267.1h.6M232.9 267.4h-.6M233.1 267.4l.5 .1M233.2 267.5h.4M233.3 267.5h.3M233.3 267.6h.4M233.4 267.8h.3M233.4 267.7h.3M233.4 269.1h.1"/>
<path d="M233.4 268.9h.3M233.4 268.8h.3M233.4 268.7h.3M233.4 268.6h.3M233.4 268.5h.3M233.4 268.4h.3M233.4 268.3h.3M233.4 268.2h.3M233.4 268.1h.3M233.4 268h.3M233.4 267.9h.3M233.6 267.4h-1.3"/>
<path d="M233.6 269l-.2 .1M233.7 269h-.3M233.7 268.9h-.3M234.1 268.7h.4M234.1 268.6h.3M234.1 267.7h.3M234.1 268.7l.4 .1M234.1 267.9h.1M234.2 268.8h.8M234.2 268.9h.8M234.3 268.9h.7M234.3 267.4h1.1"/>
<path d="M234.3 269h.7M234.3 267.3h1M234.4 269h.6M234.4 268.1h1.1M234.4 267.8l-.3 .1M234.4 267.3h.9M234.4 267.8h-.3M234.4 268.5l-.3 .1M234.4 267.7h-.3M234.4 267.2h.8M234.5 268.5h-.4M234.5 267.6h-.4"/>
<path d="M234.5 269.1h.5M234.5 268.4l-.4 .1M234.5 267.5l-.4 .1M234.5 268.1h1M234.6 267.5h-.4M234.6 267.1h.5M234.7 268.4h-.6M234.7 268h.8M234.7 269.1h.1M234.7 267.4l-.5 .1M234.8 268.3h-.6M234.8 267.9h.7"/>
<path d="M234.9 268.2l-.7 .1M234.9 267.4h.5M235 267.9h.5M235 267.5h.4M235.1 268.2h-.8M235.1 267.5l.4 .1M235.1 267.8h.4M235.2 268.2h.3M235.2 267.6h.3M235.2 267.7h.3M235.2 269.1h.1M235.2 268.9h.3"/>
<path d="M235.2 268.8h.3M235.2 268.7h.3M235.2 268.6h.3M235.2 268.5h.3M235.2 268.4h.3M235.2 268.3h.3M235.5 269l-.3 .1M235.5 269h-.3M235.9 269.1h.2M235.9 268.9h.3M235.9 268.8h.3M235.9 268.7h.3"/>
<path d="M235.9 268.6h.3M235.9 268.5h.3M235.9 268.4h.3M235.9 268.3h.3M235.9 268.2h.3M235.9 268.1h.3M235.9 268h.3M235.9 267.9h.3M235.9 267.8h.3M235.9 267.7h.3M236.1 267.3h1M236.2 267.3h.9"/>
<path d="M236.2 269l-.3 .1M236.2 269h-.3M236.2 268.9l-.3 .1M236.2 267.2h.8M236.3 267.6h-.4M236.3 267.5l-.3 .1M236.4 267.1h.5M236.4 267.5h-.4M236.5 267.4h-.5M236.7 267.4h.5M236.9 267.5h.4M237 267.6h.3"/>
<path d="M237 267.7h.3M237.2 267.8l-.2 .1M237.2 267.4h-1.1M237.3 267.8h-.3M237.7 268.5h.3M237.7 268.4h.3M237.7 268.3h.3M237.7 268.2h.3M237.7 268.1h.3M237.7 268h.3M237.7 267.9h.3M237.7 267.8h.3"/>
<path d="M237.7 267.7h.3M237.8 268.6h.3M237.8 268.5l.3 .1M237.8 268.7h.3M237.8 268.7l.4 .1M237.8 268.8h1.2M237.9 268.9h1.1M237.9 267.3h1.2M237.9 268.9h1M238 267.3h1.1M238.1 269h.7M238.1 267.7h-.4"/>
<path d="M238.1 267.2h1M238.1 267.6h-.3M238.2 269.1h.5M238.2 267.1h.5M238.2 267.5h-.4M238.3 267.4l-.5 .1M238.4 269.1h.1M238.5 267.4h.6M238.7 267.5h.4M238.7 268.7h.4M238.8 267.6h.3M238.8 268.5h.3"/>
<path d="M238.8 268.4h.3M238.8 268.3h.3M238.8 268.2h.3M238.8 268.1h.3M238.8 268h.3M238.8 267.9h.3M238.8 267.8h.3M238.8 267.7h.3M238.8 267.1h.3M238.8 267h.3M238.8 266.9h.3M238.8 266.8h.3"/>
<path d="M238.8 266.7h.3M238.8 266.6h.3M238.8 266.5h.3M238.9 269h-.9M238.9 266.5h.2M239.1 268.8h-.5M239.1 268.6h-.3M239.1 268.5l-.3 .1M239.1 267.4h-1.2M239.4 268.6h.3M239.4 268.5h.3M239.4 268.4h.3"/>
<path d="M239.4 268.3h.3M239.4 268.2h.3M239.4 268.1h.3M239.4 268h.3M239.4 267.9h.3M239.4 267.8h.3M239.4 267.7h.3M239.4 267.6h.3M239.4 267.5h.3M239.4 267.4h.3M239.4 267.3h.3M239.4 268.8h1.7"/>
<path d="M239.4 268.7l.4 .1M239.4 268.7h.3M239.4 267.2h.3M239.5 268.9h1.5M239.5 269h1.4M239.6 269h1.3M239.6 267.1h.1M239.7 269.1h.4M239.9 269.1h.1M240 268.8h.5M240.1 268.7h.3M240.1 268.6h.3"/>
<path d="M240.1 268.5h.3M240.1 268.4h.3M240.1 268.3h.3M240.1 268.2h.3M240.1 268.1h.3M240.1 268h.3M240.1 267.9h.3M240.1 267.8h.3M240.1 267.7h.3M240.1 267.6h.3M240.1 267.5h.3M240.1 267.4h.3"/>
<path d="M240.1 267.3h.3M240.1 267.2h.3M240.2 267.2h.2M240.3 267.1h.1M240.4 269.1h.4M240.8 268.7h.3M240.8 268.6h.3M240.8 268.5h.3M240.8 268.4h.3M240.8 268.3h.3M240.8 268.2h.3M240.8 268.1h.3"/>
<path d="M240.8 268h.3M240.8 267.9h.3M240.8 267.8h.3M240.8 267.7h.3M240.8 267.6h.3M240.8 267.5h.3M240.8 267.4h.3M240.8 267.3h.3M240.9 267.2h.2M241 267.1h.1M241 268.9h-1.5M241.1 268.7l-.4 .1"/>
<path d="M241.4 268.7h.3M241.4 268.6h.3M241.4 268.5h.3M241.4 268.7l.4 .1M241.4 267.9h.1M241.4 267.7h.3M241.4 268.8h.8M241.4 268.9h.9M241.5 268.9h.8M241.5 267.4h1.1M241.6 267.3h1M241.6 269h.7"/>
<path d="M241.6 267.8l-.2 .1M241.6 267.3h.9M241.7 267.8h-.3M241.7 267.7l-.3 .1M241.7 268.5h-.3M241.7 267.6h-.3M241.7 267.2h.7M241.7 269.1h.6M241.8 268.4l-.4 .1M241.8 268.1h.9M241.8 267.5l-.4 .1M241.8 267.1h.5"/>
<path d="M241.8 267.5h-.4M241.9 268.4h-.5M241.9 268h.8M242 267.4l-.6 .1M242 268.3h-.6M242.1 267.9h.6M242.1 267.4l.6 .1M242.2 268.2l-.7 .1M242.2 267.9h.5M242.3 267.5h.4M242.3 268.2h-.7M242.4 267.8h.3"/>
<path d="M242.4 267.5l.3 .1M242.4 267.6h.3M242.4 268.2h.3M242.4 267.7h.3M242.5 269.1h.1M242.5 269h.2M242.5 268.9h.2M242.5 268.8h.2M242.5 268.7h.2M242.5 268.6h.2M242.5 268.5h.2M242.5 268.4h.2"/>
<path d="M242.5 268.3h.2M242.5 268.2h.2M242.7 269l-.2 .1M242.7 268.1h-1.1M243.2 269.1h.1M243.2 269h.3M243.2 268.9h.3M243.2 268.8h.3M243.2 268.7h.3M243.2 268.6h.3M243.2 268.5h.3M243.2 268.4h.3"/>
<path d="M243.2 268.3h.3M243.2 268.2h.3M243.2 268.1h.3M243.2 268h.3M243.2 267.9h.3M243.2 267.8h.3M243.2 267.7h.3M243.2 267.5h.4M243.3 267.4h1.2M243.4 267.3h1M243.4 267.3h.9M243.5 269l-.3 .1"/>
<path d="M243.5 267.2h.8M243.5 267.6h-.3M243.6 267.1h.5M243.6 267.5h-.4M243.8 267.4l-.5 .1M244 267.4h.5M244.1 267.5h.4M244.2 267.5l.3 .1M244.2 267.6h.4M244.2 267.7h.4M244.3 267.8h.2M244.5 267.8h-.2"/>
<path d="M245 268.6h.4M245 268.5l.3 .1M245 268.5h.3M245 268h1.2M245 268h.3M245 267.9h.3M245 267.8h.3M245 267.7h.3M245 267.6h.3M245 268.7h.4M245.1 268.7l.4 .1M245.1 268.8h1.2"/>
<path d="M245.1 268.9h1.1M245.2 268.9h1M245.2 267.3h1M245.2 267.3h.9M245.3 269h.8M245.3 267.2h.8M245.3 267.7h-.3M245.3 268.4h-.3M245.4 267.5l-.4 .1M245.4 269.1h.5M245.4 267.1h.5M245.4 267.5h-.3"/>
<path d="M245.5 268.4h-.5M245.6 267.4l-.5 .1M245.6 268.3h-.6M245.6 269.1h.1M245.7 268.2l-.7 .1M245.8 267.9h.6M245.8 267.4l.5 .1M245.9 268.2h-.9M245.9 267.5h.4M245.9 267.8h.5M246 267.5h.3M246 268.6h.3"/>
<path d="M246 267.6h.3M246.1 268.6h.3M246.1 268.1h-1.1M246.1 267.8h.3M246.1 267.7h.3M246.1 268.4h.3M246.3 268.3h.1M246.3 267.4h-1.2M246.3 268.8h-.4M246.3 268h-.8M246.3 268.7h-.3M246.4 267.9h-.8"/>
<path d="M246.4 268.5h-.3M253.9 268.4l.5 .1M253.9 268.4h.4M253.9 268.3h.4M253.9 268.2h.4M253.9 268.1h.4M253.9 268h.4M253.9 267.9h.4M253.9 267.8h.4M253.9 267.7h.4M254 268.5l.4 .1M254 268.5h.4"/>
<path d="M254 268.6h.5M254 268.7h1.3M254 267.3h1.3M254.1 268.8h1.2M254.1 267.3h1.2M254.1 268.9h1.1M254.1 267.2h1.1M254.2 267.1h1M254.3 269h.8M254.3 267.1h.8M254.3 269h.7M254.3 267.6l-.4 .1"/>
<path d="M254.4 267.5l-.4 .1M254.4 267.5h-.4M254.4 267h.5M254.5 267.4l-.5 .1M254.5 269.1h.3M254.8 267.4h.6M254.9 267.5h.5M255 268.5h.4M255 267.5h.4M255 267.6h.4M255 268.4h.4M255 268.3h.4"/>
<path d="M255 268.2h.4M255 268.1h.4M255 268h.4M255 267.9h.4M255 267.8h.4M255 267.7h.4M255.2 268.9h-1M255.3 267.4h-1.3M255.4 268.6h-.6M255.4 268.6h-.5M255.9 269.5h.3M255.9 269.4h.3"/>
<path d="M255.9 269.3h.3M255.9 269.2h.3M255.9 269.1h.3M255.9 268.7h1.4M255.9 268.6h.5M255.9 268.5l.4 .1M255.9 268.5h.4M255.9 268.4h.3M255.9 268.3h.3M255.9 268.2h.3M255.9 268.1h.3M255.9 268h.3"/>
<path d="M255.9 267.9h.3M255.9 267.8h.3M255.9 267.7h.3M255.9 267.6h.3M255.9 269.8h.1M255.9 267.4h1.4M255.9 267.3h1.3M256 267.3h1.2M256 267.2h1.1M256.1 267.1h1M256.1 269.7l-.2 .1M256.2 267.1h.8"/>
<path d="M256.2 269.7h-.3M256.2 269.6h-.3M256.3 267.5l-.4 .1M256.3 267.5h-.4M256.3 267h.6M256.4 267.4h-.5M256.5 269.1h.2M256.8 267.4l.5 .1M256.9 267.5h.4M256.9 267.5l.4 .1M256.9 269l-1 .1M256.9 268.4h.4"/>
<path d="M256.9 267.7h.4M256.9 267.6h.4M256.9 268.3h.4M256.9 268.2h.4M256.9 268.1h.4M256.9 268h.4M256.9 267.9h.4M256.9 267.8h.4M257 269h-1.1M257.1 268.9l-1.2 .1M257.1 268.9h-1.2M257.2 268.8h-1.3"/>
<path d="M257.2 268.7l-1.3 .1M257.3 268.6h-.5M257.3 268.6h-.4M257.3 268.5h-.4M257.6 274.7v3.9M257.8 268.5h.4M257.8 268.4l.4 .1M257.8 267.9h1.4M257.8 267.8l.3 .1M257.8 267.8h.3M257.8 267.7h.3M257.8 267.5h.4"/>
<path d="M257.8 268.6h.5M257.8 268.5l.5 .1M257.8 268.7h1.3M257.9 267.3h1.2M257.9 268.8h1.2M258 267.2h1M258 267.1h1M258.1 269h.8M258.1 267.1h.8M258.1 269h.7M258.2 267.6h-.4M258.2 267h.6"/>
<path d="M258.3 268.4h-.5M258.3 267.5h-.5M258.3 267.9h.9M258.3 267.4l-.5 .1M258.4 269.1h.2M258.4 268.3h-.6M258.4 267.8h.8M258.5 268.2l-.7 .1M258.6 267.8h.6M258.7 268.2h-.9M258.7 267.7h.5M258.7 267.4h.5"/>
<path d="M258.7 267.5h.5M258.8 268.6h.4M258.8 267.7h.4M258.8 267.5h.4M258.8 268.5h.4M258.8 268.1h-1M258.8 268.4h.4M258.8 268.3h.4M258.9 268.3h.3M258.9 268l-1.1 .1M259 268.9h-1M259 268.2h.2"/>
<path d="M259.1 268h-1.3M259.1 268.7l-1.2 .1M259.2 267.4h-1.4M259.2 268.6h-.5M259.7 269h.2M259.7 268.9h.4M259.7 268.8h.4M259.7 268.7h.4M259.7 268.6h.4M259.7 268.5h.4M259.7 268.4h.4M259.7 268.3h.4"/>
<path d="M259.7 268.2h.4M259.7 268.1h.4M259.7 268h.4M259.7 267.9h.4M259.7 267.8h.4M259.7 267.7h.4M259.8 267.3h1.2M259.9 267.2h1.1M259.9 267.1h1M260 269h-.3M260 267.1h.8M260.1 268.9l-.4 .1"/>
<path d="M260.1 267.6h-.4M260.1 267.5l-.4 .1M260.2 267.5h-.5M260.2 267h.5M260.2 267.4l-.5 .1M260.6 267.4l.5 .1M260.7 267.5h.4M260.8 269h.2M260.8 268.9h.4M260.8 268.8h.4M260.8 268.7h.4M260.8 268.6h.4"/>
<path d="M260.8 268.5h.4M260.8 268.4h.4M260.8 268.3h.4M260.8 268.2h.4M260.8 268.1h.4M260.8 268h.4M260.8 267.9h.4M260.8 267.8h.4M260.8 267.7h.4M260.8 267.6h.4M261.1 269h-.3M261.1 267.4h-1.4"/>
<path d="M261.2 268.9l-.4 .1M262.8 266.6h.3M262.8 269.1h.1M262.8 268.9h.3M262.8 268.8h.3M262.8 268.7h.3M262.8 268.6h.3M262.8 268.5h.3M262.8 268.4h.3M262.8 268.3h.3M262.8 268.2h.3M262.8 268.1h.3"/>
<path d="M262.8 268h.3M262.8 267.9h.3M262.8 267.8h.3M262.8 267.7h.3M262.8 267.3h1.2M262.8 267.2l1.1 .1M262.8 267.2h1M262.8 267.1h.3M262.8 267h.3M262.8 266.9h.3M262.8 266.8h.3M262.8 266.7h.3"/>
<path d="M262.8 266.5h.3M262.9 266.5h.2M263 269l-.2 .1M263.1 269h-.3M263.1 267.7l-.3 .1M263.1 267.6h-.3M263.2 267.5l-.4 .1M263.2 267.5h-.4M263.2 267.1h.5M263.4 267.4h-.6M263.6 267.4l.5 .1M263.7 267.5h.4"/>
<path d="M263.8 267.5h.3M263.8 267.6h.3M263.9 267.8h.3M263.9 267.7h.3M263.9 269.1h.1M263.9 268.9h.3M263.9 268.8h.3M263.9 268.7h.3M263.9 268.6h.3M263.9 268.5h.3M263.9 268.4h.3M263.9 268.3h.3"/>
<path d="M263.9 268.2h.3M263.9 268.1h.3M263.9 268h.3M263.9 267.9h.3M264 267.4h-1.2M264.1 269l-.2 .1M264.1 269h-.2M264.2 268.9h-.3M264.6 268.7h.4M264.6 268.6h.3M264.6 267.7h.3M264.6 268.7l.4 .1"/>
<path d="M264.6 267.9h.1M264.6 268.8h.9M264.7 268.9h.8M264.7 267.4h1.2M264.8 269h.7M264.8 267.3h1M264.9 268.1h1.1M264.9 267.8l-.3 .1M264.9 267.3h.8M264.9 267.8h-.3M264.9 268.5l-.3 .1M264.9 267.7h-.3"/>
<path d="M264.9 267.2h.8M264.9 268.5h-.3M264.9 267.6h-.3M265 269.1h.5M265 268.4l-.4 .1M265 267.5l-.4 .1M265 268.1h1M265 267.5h-.3M265 267.1h.6M265.1 268.4h-.5M265.2 268h.8M265.2 267.4l-.5 .1"/>
<path d="M265.2 269.1h.1M265.3 268.3h-.7M265.3 267.9h.7M265.4 268.2l-.7 .1M265.4 267.4h.5M265.5 267.9h.5M265.5 267.5h.4M265.6 268.2h-.8M265.6 267.5l.4 .1M265.6 267.8h.4M265.6 268.2h.4M265.6 267.6h.4"/>
<path d="M265.7 267.7h.3M265.7 269.1h.1M265.7 268.9h.3M265.7 268.8h.3M265.7 268.7h.3M265.7 268.6h.3M265.7 268.5h.3M265.7 268.4h.3M265.7 268.3h.3M265.7 268.2h.3M266 269l-.3 .1M266 269h-.3"/>
<path d="M266.4 269.1h.1M266.4 268.9h.3M266.4 268.8h.3M266.4 268.7h.3M266.4 268.6h.3M266.4 268.5h.3M266.4 268.4h.3M266.4 268.3h.3M266.4 268.2h.3M266.4 268.1h.3M266.4 268h.3M266.4 267.9h.3"/>
<path d="M266.4 267.8h.3M266.4 267.7h.3M266.6 267.3h1M266.6 267.3h.9M266.7 269l-.3 .1M266.7 269h-.3M266.7 268.9l-.3 .1M266.7 267.2h.8M266.8 267.6h-.4M266.8 267.5l-.4 .1M266.8 267.1h.6M266.9 267.5h-.4"/>
<path d="M267 267.4h-.5M267.2 267.4h.5M267.3 267.5h.4M267.4 267.5h.4M267.4 267.6h.4M267.5 267.7h.3M267.5 267.8h.2M267.7 267.4h-1.2M267.8 267.8h-.3M268.2 268.4h.3M268.2 268.3h.3M268.2 268.2h.3"/>
<path d="M268.2 268.1h.3M268.2 268h.3M268.2 267.9h.3M268.2 267.8h.3M268.2 268.5h.3M268.2 267.7h.3M268.2 268.6h.4M268.2 268.5l.3 .1M268.3 268.7h.3M268.3 268.7l.4 .1M268.3 268.8h1.2M268.4 268.9h1.1"/>
<path d="M268.4 267.3h1.2M268.4 268.9h1M268.5 267.3h1.1M268.5 269h.8M268.5 267.2h1.1M268.6 267.6l-.4 .1M268.6 267.5l-.3 .1M268.6 269.1h.6M268.6 267.1h.6M268.7 267.5h-.4M268.8 267.4l-.5 .1M268.8 269.1h.1"/>
<path d="M268.9 269.1h.1M269 267.4h.6M269.2 267.5h.4M269.3 267.6h.3M269.3 268.5h.3M269.3 268.4h.3M269.3 268.3h.3M269.3 268.2h.3M269.3 268.1h.3M269.3 268h.3M269.3 267.9h.3M269.3 267.8h.3"/>
<path d="M269.3 267.7h.3M269.3 267.1h.3M269.3 267h.3M269.3 266.9h.3M269.3 266.8h.3M269.3 266.7h.3M269.3 266.6h.3M269.3 266.5h.3M269.3 269h-.8M269.4 266.5h.2M269.5 268.8h-.4M269.6 268.7h-.4"/>
<path d="M269.6 268.6h-.4M269.6 268.5l-.3 .1M269.6 267.4h-1.2M269.9 268.6h.3M269.9 268.5h.3M269.9 268.4h.3M269.9 268.3h.3M269.9 268.2h.3M269.9 268.1h.3M269.9 268h.3M269.9 267.9h.3M269.9 267.8h.3"/>
<path d="M269.9 267.7h.3M269.9 267.6h.3M269.9 267.5h.3M269.9 267.4h.3M269.9 267.3h.3M269.9 268.8h1.6M269.9 268.7l.3 .1M269.9 268.7h.3M269.9 268.9h1.6M269.9 267.2h.3M270 268.9h1.5M270 269h1.4"/>
<path d="M270 267.1h.2M270.2 269.1h.4M270.4 269.1h.1M270.5 268.8h.4M270.6 268.7h.3M270.6 268.6h.3M270.6 268.5h.3M270.6 268.4h.3M270.6 268.3h.3M270.6 268.2h.3M270.6 268.1h.3M270.6 268h.3"/>
<path d="M270.6 267.9h.3M270.6 267.8h.3M270.6 267.7h.3M270.6 267.6h.3M270.6 267.5h.3M270.6 267.4h.3M270.6 267.3h.3M270.6 267.2h.3M270.7 267.1h.2M270.8 269.1h.5M271.3 268.7h.3M271.3 268.6h.3"/>
<path d="M271.3 268.5h.3M271.3 268.4h.3M271.3 268.3h.3M271.3 268.2h.3M271.3 268.1h.3M271.3 268h.3M271.3 267.9h.3M271.3 267.8h.3M271.3 267.7h.3M271.3 267.6h.3M271.3 267.5h.3M271.3 267.4h.3"/>
<path d="M271.3 267.3h.3M271.3 267.2h.3M271.4 267.1h.1M271.6 268.7l-.4 .1M271.8 268.7h.4M271.8 268.6h.4M271.8 268.5h.4M271.9 268.7l.3 .1M271.9 267.9h.1M271.9 267.7h.2M271.9 268.8h.8M271.9 268.9h.8"/>
<path d="M272 268.9h.8M272 267.3h1.1M272.1 269h.7M272.1 267.8l-.2 .1M272.1 267.3h.9M272.1 267.8h-.2M272.2 267.7h-.3M272.2 268.5h-.4M272.2 267.6h-.3M272.2 267.2h.7M272.2 269.1h.5M272.2 268.4l-.3 .1"/>
<path d="M272.2 268.1h1M272.2 267.5l-.3 .1M272.3 267.1h.5M272.3 267.5h-.4M272.4 268.4h-.5M272.4 268h.8M272.4 267.4l-.5 .1M272.5 268.3h-.6M272.6 267.9h.6M272.6 267.4l.6 .1M272.6 268.2l-.7 .1M272.7 267.9h.5"/>
<path d="M272.8 267.5h.4M272.8 268.2h-.8M272.8 267.5l.4 .1M272.9 267.8h.3M272.9 267.6h.3M272.9 268.2h.3M272.9 267.7h.3M272.9 269.1h.1M272.9 269h.3M272.9 268.9h.3M272.9 268.8h.3M272.9 268.7h.3"/>
<path d="M272.9 268.6h.3M272.9 268.5h.3M272.9 268.4h.3M272.9 268.3h.3M273.1 267.4h-1.1M273.2 269l-.3 .1M273.2 268.1h-1.1M273.7 269.1h.1M273.7 268.9h.2M273.7 268.8h.2M273.7 268.7h.2M273.7 268.6h.2"/>
<path d="M273.7 268.5h.2M273.7 268.4h.2M273.7 268.3h.2M273.7 268.2h.2M273.7 268.1h.2M273.7 268h.2M273.7 267.9h.2M273.7 267.8h.2M273.7 267.7h.3M273.7 267.5h.3M273.8 267.4h1.1M273.8 267.3h1.1"/>
<path d="M273.9 267.3h.9M273.9 269l-.2 .1M273.9 269h-.2M274 267.2h.7M274 267.6h-.3M274.1 267.1h.5M274.1 267.5h-.4M274.3 267.4l-.6 .1M274.4 267.4l.6 .1M274.6 267.5h.4M274.7 267.5l.3 .1M274.7 267.6h.3"/>
<path d="M274.7 267.7h.3M274.9 267.8l-.2 .1M275 267.8h-.3M275.5 268.6h.3M275.5 268.5l.3 .1M275.5 268.5h.3M275.5 268h1.1M275.5 268h.3M275.5 267.9h.3M275.5 267.8h.3M275.5 267.7h.3M275.5 267.6h.3"/>
<path d="M275.5 268.7h.4M275.5 268.7l.4 .1M275.6 268.8h1.1M275.6 267.4h1.1M275.6 268.9h1.1M275.7 268.9h.9M275.7 267.3h1M275.7 267.3h.9M275.7 269h.9M275.8 269h.7M275.8 267.2h.7M275.8 267.7h-.3"/>
<path d="M275.8 268.4h-.3M275.9 267.5l-.4 .1M275.9 269.1h.5M275.9 267.1h.5M275.9 267.5h-.4M276 268.4h-.5M276.1 267.4l-.5 .1M276.1 268.3h-.6M276.1 269.1h.1M276.2 268.2l-.7 .1M276.2 267.9h.6M276.2 267.4l.6 .1"/>
<path d="M276.4 268.2h-.9M276.4 267.8h.4M276.4 267.5h.4M276.5 267.5h.3M276.5 268.6h.3M276.5 267.6h.3M276.5 267.8h.3M276.5 267.7h.3M276.5 268.1h-1M276.6 268.5h.2M276.6 268.4h.2M276.7 268.3h.1"/>
<path d="M276.8 268.8h-.4M276.8 268h-.8M276.8 268.7h-.4M276.8 268.6h-.3M276.8 267.9h-.7M305.1 274.7v3.9M313.6 264.6h86.4M313.6 269.7h86.4M352.6 274.7v3.9M400 274.6h.1"/>
<circle cx="29.2" cy="248.1" r="2.03"/>
<circle cx="29.2" cy="248.1" r=".51"/>
<circle cx="67.3" cy="248.1" r="2.03"/>
<circle cx="67.3" cy="248.1" r=".51"/>
<circle cx="29.2" cy="263.3" r="2.03"/>
<circle cx="29.2" cy="263.3" r=".51"/>
<circle cx="67.3" cy="263.3" r="2.03"/>
<circle cx="67.3" cy="263.3" r=".51"/>
</g>
<path d="M210.8 88.1h5.1v83.8h-5.1zM264.1 88.1h5.1v83.8h-5.1zM317.5 88.1h5v83.8h-5z" fill="none" stroke="#000" stroke-width=".42"/>
<g fill="none" stroke="#000" stroke-width=".61">
<path d="M20.3 22.1h379.7v252.6h-379.7zM212.1 98.3h1.2M212.1 95.7h1.2M212.1 93.2h1.2M212.1 90.6h1.2M265.4 98.3h1.3M265.4 95.7h1.3M265.4 93.2h1.3M265.4 90.6h1.3M318.7 98.3h1.3M318.7 95.7h1.3M318.7 93.2h1.3"/>
<path d="M318.7 90.6h1.3M212.1 118.6h1.2M212.1 116h1.2M212.1 113.5h1.2M212.1 110.9h1.2M212.1 108.4h1.2M212.1 105.9h1.2M212.1 103.3h1.2M212.1 100.8h1.2M265.4 118.6h1.3M265.4 116h1.3M265.4 113.5h1.3"/>
<path d="M265.4 110.9h1.3M265.4 108.4h1.3M265.4 105.9h1.3M265.4 103.3h1.3M265.4 100.8h1.3M318.7 118.6h1.3M318.7 116h1.3M318.7 113.5h1.3M318.7 110.9h1.3M318.7 108.4h1.3M318.7 105.9h1.3M318.7 103.3h1.3"/>
<path d="M318.7 100.8h1.3M212.1 138.9h1.2M212.1 136.3h1.2M212.1 133.8h1.2M212.1 131.3h1.2M212.1 128.7h1.2M212.1 126.2h1.2M212.1 123.6h1.2M212.1 121.1h1.2M265.4 138.9h1.3M265.4 136.3h1.3M265.4 133.8h1.3"/>
<path d="M265.4 131.3h1.3M265.4 128.7h1.3M265.4 126.2h1.3M265.4 123.6h1.3M265.4 121.1h1.3M318.7 138.9h1.3M318.7 136.3h1.3M318.7 133.8h1.3M318.7 131.3h1.3M318.7 128.7h1.3M318.7 126.2h1.3M318.7 123.6h1.3"/>
<path d="M318.7 121.1h1.3M212.1 159.2h1.2M212.1 156.7h1.2M212.1 154.1h1.2M212.1 151.6h1.2M212.1 149h1.2M212.1 146.5h1.2M212.1 144h1.2M212.1 141.4h1.2M265.4 159.2h1.3M265.4 156.7h1.3M265.4 154.1h1.3"/>
<path d="M265.4 151.6h1.3M265.4 149h1.3M265.4 146.5h1.3M265.4 144h1.3M265.4 141.4h1.3M318.7 159.2h1.3M318.7 156.7h1.3M318.7 154.1h1.3M318.7 151.6h1.3M318.7 149h1.3M318.7 146.5h1.3M318.7 144h1.3"/>
<path d="M318.7 141.4h1.3M212.1 169.4h1.2M212.1 166.8h1.2M212.1 164.3h1.2M212.1 161.7h1.2M265.4 169.4h1.3M265.4 166.8h1.3M265.4 164.3h1.3M265.4 161.7h1.3M318.7 169.4h1.3M318.7 166.8h1.3M318.7 164.3h1.3"/>
<path d="M318.7 161.7h1.3M313.6 244.3v30.4M400 244.3h-116.8v30.4"/>
</g>
<path d="M16.5 18.2h387.3v260.4h-387.3z" fill="none" stroke="#000" stroke-width=".32"/>
<path d="M154.5 191.3h3.3v.9h-3.3zM164.7 191.3h3.3v.9h-3.3zM174.9 191.3h3.3v.9h-3.3z" fill="#000" stroke="#000" stroke-width=".25"/>
<g fill="none" stroke="#000" stroke-width=".38">
<path d="M230.4 257.3l1-1 1.4 1.2 1.2-.6 .2-1.8h1.4l.2 1.8 1.2 .6 1.4-1.2 1 1M230.4 257.3l1.2 1.4-.5 1.2-1.8 .2v1.4M230.4 257.3h2.2M230.7 257.6h8.4M230.8 256.9h1.4M231 258h7.9M231.1 256.6h.7M231.2 259.7h2.3M231.3 259.4h2.6M231.3 258.3h7.3M231.4 259h7M231.6 258.7h6.7"/>
<path d="M233.2 257.3h3.5M233.5 259.7l-.3 .5v.9M234 256.9h1.8M234.1 256.6h1.7M234.1 256.2h1.6M234.1 255.9h1.6M234.2 255.5h1.5M234.2 255.2h1.4M234.8 259l-.8 .3-.5 .4M235.1 259l.8 .3 .4 .4M236 259.4h2.6M236.3 259.7l.3 .5 .1 .9"/>
<path d="M236.3 259.7h2.4M237.2 257.3h2.2M237.7 256.9h1.4M238.1 256.6h.6M239.4 257.3l-1.1 1.4 .5 1.2 1.8 .2v1.4M260.9 257.3h2.2M260.9 257.3l1.2 1.4-.5 1.2-1.9 .2v1.4M261.2 257.6h8.4M261.3 256.9h1.4M261.5 258h7.8M261.6 256.6h.6M261.6 259.7h2.4"/>
<path d="M261.7 259.4h2.6M261.7 258.3h7.3M261.9 259h7M262 258.7h6.8M263.7 257.3h3.4M263.7 257.2l.8-.3 .2-1.8h1.4l.2 1.8 .8 .3M263.7 257.2l-.4 .3-1.4-1.2-1 1M264 259.7l-.4 1.1M264.5 256.9h1.8M264.6 256.6h1.6M264.6 256.2h1.6M264.6 255.9h1.6"/>
<path d="M264.7 255.5h1.4M264.7 255.2h1.4M265.3 259l-.9 .3-.4 .4M265.6 259l.5 .1 .7 .6M266.5 259.4h2.5M266.8 259.7h2.4M266.8 259.7l.3 .5 .1 .9M267.1 257.2l.4 .3 1.4-1.2 1 1M267.7 257.3h2.2M268.1 256.9h1.5M268.6 256.6h.6M269.9 257.3l-1.2 1.4 .5 1.2 1.9 .2v1.4"/>
<path d="M229.3 261.5l1.8 .2 .5 1.1M229.3 261.5h4M229.3 261.1h3.9M229.3 260.8h3.9M229.3 260.4h3.9M229.6 260.1h3.7M230.5 264.2h2.2M230.7 264.6h1.6M230.8 263.9h2.8M231 263.5h2.8M231.1 264.9h.7M231.1 261.8h2.4"/>
<path d="M231.2 262.1h2.6M231.3 263.2h2.6M231.4 262.5h2.8M231.6 262.8h2.5M233.1 264.2h.4M233.2 261.1l.3 .8 .7 .5-.8 2-.6-.3-1.4 1.2-1-1 1.2-1.5M235.6 262.5h2.9M235.8 262.8h2.5M235.9 263.2h2.6M236.1 263.5h2.7M236.1 262.1h2.5M236.2 263.9h2.9"/>
<path d="M236.3 264.2h.5M236.4 261.8h2.3M236.5 260.1h3.8M236.6 261.5h4M236.7 260.4h3.9M236.7 261.1l-.4 .8-.7 .5 .8 2 .6-.3 1.4 1.2 1-1-1.1-1.5 .2-.3M236.7 261.1h3.9M236.7 260.8h3.9M237.2 264.2h2.2M237.6 264.6h1.5M238 264.9h.8M240.6 261.5l-1.8 .2-.3 .8"/>
<path d="M259.7 261.5h4.1M259.7 261.1h4M259.7 260.8h3.9M259.7 260.4h4M259.7 261.5l1.9 .2 .3 .8M260.1 260.1h3.7M260.9 264.2h2.3M261.2 264.6h1.5M261.2 263.9h2.9M261.5 263.5h2.8M261.5 264.9h.8M261.6 261.8h2.3"/>
<path d="M261.7 262.1h2.6M261.8 263.2h2.6M261.9 262.5l.2 .3M261.9 262.5h2.8M262.1 262.8h2.4M263.5 264.2h.5M263.6 260.8v.3M263.6 261.1l.4 .8 .7 .5-.8 2-.6-.3-1.4 1.2-1-1 1.2-1.5M266.1 262.5h2.8M266.3 262.8h2.4M266.4 263.2h2.6M266.6 263.5h2.7"/>
<path d="M266.6 262.1h2.5M266.7 263.9h2.9M266.8 264.2h.5M266.9 261.8h2.3M267 260.1h3.7M267.1 261.5h4M267.1 260.4h4M267.2 261.1h3.9M267.2 261.1l-.4 .8-.7 .5 .8 2 .6-.3 1.4 1.2 1-1-1.2-1.5M267.2 260.8h3.9M267.6 264.2h2.3M268.1 264.6h1.5"/>
<path d="M268.5 264.9h.8M268.9 262.5l-.2 .3M271.1 261.5l-1.9 .2-.3 .8"/>
</g>
<g fill="#000" stroke="#000" stroke-width=".25">
<path d="M27.2 248.1h1.5l.2 .4 .3 .1v1.5a2 2 0 0 1-2-2z" fill-rule="evenodd"/>
<path d="M29.2 246a2.04 2.04 0 0 1 2 2.1h-1.5l-.1-.3-.4-.2z" fill-rule="evenodd"/>
<path d="M65.7 246.8l.6-.5 1-.3v1.6l-.4 .2-.1 .3h-1.5v-.6z" fill-rule="evenodd"/>
<path d="M67.3 248.6l.3-.1 .2-.4h1.5a2.04 2.04 0 0 1-2 2z" fill-rule="evenodd"/>
<path d="M27.2 263.3h1.5l.2 .4 .3 .1v1.5a2 2 0 0 1-2-2z" fill-rule="evenodd"/>
<path d="M29.2 261.3a2.04 2.04 0 0 1 2 2h-1.5l-.1-.3-.4-.2z" fill-rule="evenodd"/>
<path d="M65.7 262l.6-.5 1-.2v1.5l-.4 .2-.1 .3h-1.5v-.6z" fill-rule="evenodd"/>
<path d="M67.8 263.3h1.5a2.04 2.04 0 0 1-2 2v-1.5l.3-.1z" fill-rule="evenodd"/>
</g>
<use href="#words"/>
</svg>
